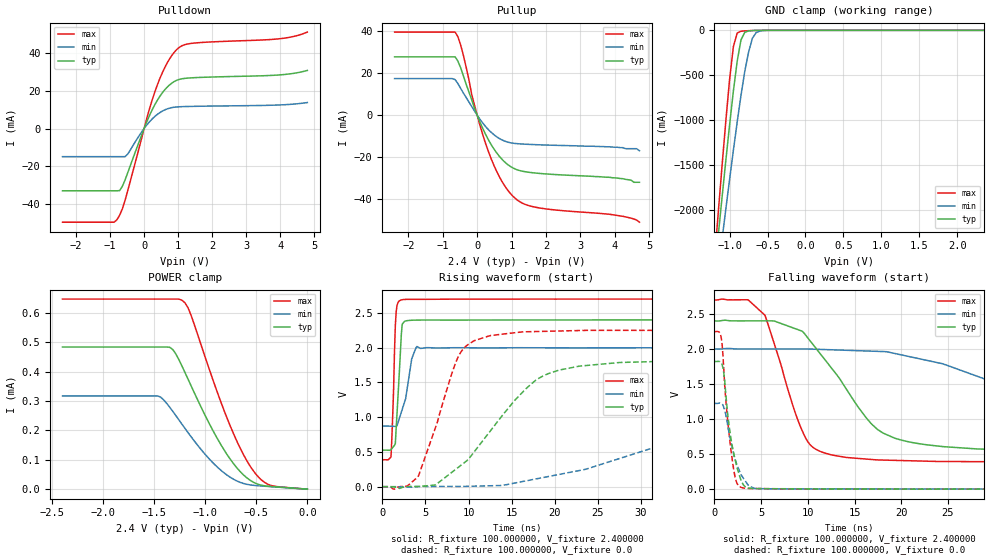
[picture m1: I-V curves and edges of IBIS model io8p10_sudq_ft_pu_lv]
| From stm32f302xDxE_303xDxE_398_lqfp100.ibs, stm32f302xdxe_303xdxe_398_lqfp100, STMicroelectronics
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|   Model io8p10_sudq_ft_pu_lv
[Model]  io8p10_sudq_ft_pu_lv
Model_type I/O
Polarity   Non-Inverting
Enable   Active-Low
Vinl =   0.720000V
Vinh =   1.680000V
Vmeas =  1.200000V
Cref =   50.000000pF
Rref =   100.000000M
Vref =   0.0V
C_comp   1.970100pF   1.887900pF   2.069400pF
[Temperature Range]   25.000000   0.125000k   -40.000000
[Pullup Reference]   2.400000V   2.000000V   2.700000V
[Pulldown Reference]   0.0V   0.0V   0.0V
[POWER Clamp Reference]   2.400000V   2.000000V   2.700000V
[GND Clamp Reference]   0.0V   0.0V   0.0V
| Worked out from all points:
|   slope of the pulldown table from 0 to 0.36 V, typ, clamps not added: 25.5 ohm
|   slope of the pullup table from 0 to 0.36 V, typ, clamps not added: 28.4 ohm
|   GND clamp passes 1 mA (typ) near -0.64 V on its own axis
|   rising waveform, R_fixture 100.000000, V_fixture 2.400000: 20-80 % time 500ps typ, 1.06ns min, 335ps max; typ from 0.527 V to 2.4 V
|   rising waveform, R_fixture 100.000000, V_fixture 0.0: 20-80 % time 7.39ns typ, 21.1ns min, 3.53ns max; typ from 0.001 V to 1.82 V
|   falling waveform, R_fixture 100.000000, V_fixture 2.400000: 20-80 % time 6.28ns typ, 17.7ns min, 3.33ns max; typ from 2.4 V to 0.527 V
|   falling waveform, R_fixture 100.000000, V_fixture 0.0: 20-80 % time 1.16ns typ, 1.4ns min, 916ps max; typ from 1.82 V to 0.001 V
[Pulldown]
|Voltage   I(typ)   I(min)   I(max)
-2.4V     -33.16mA   -14.98mA   -49.86mA
-880mV    -33.16mA   -14.98mA   -49.86mA
-800mV    -33.16mA   -14.98mA   -48.55mA
-640mV    -30.75mA   -14.98mA   -42.77mA
-480mV    -23.43mA   -13.57mA   -32.92mA
80mV      3.651mA    1.905mA    5.506mA
400mV     15.37mA    7.665mA    23.73mA
720mV     22.75mA    10.69mA    36.23mA
1.04V     26.18mA    11.57mA    43.27mA
1.52V     27.09mA    11.81mA    45.55mA
4V        28.55mA    12.55mA    47.81mA
4.8V      30.9mA     13.81mA    51.31mA
[Pullup]
|Voltage   I(typ)   I(min)   I(max)
-2.4V     27.74mA    17.38mA    39.53mA
-640mV    27.74mA    16.88mA    39.53mA
-560mV    25.73mA    15.04mA    37.34mA
-480mV    22.58mA    12.74mA    33.42mA
-80mV     3.427mA    2.071mA    4.957mA
160mV     -6.219mA   -3.715mA   -9.137mA
320mV     -11.51mA   -6.781mA   -16.98mA
720mV     -21mA      -11.8mA    -31.53mA
1.12V     -25.77mA   -13.54mA   -39.82mA
1.76V     -27.69mA   -14.12mA   -44.07mA
3.84V     -29.6mA    -15.1mA    -47.2mA
4.72V     -32mA      -17mA      -51mA
[GND_clamp]
|Voltage   I(typ)   I(min)   I(max)
-2.4V     -9.788A    -9.782A    -9.734A
-1.2V     -2.718A    -3.02A     -2.568A
-1.15V    -2.29A     -2.675A    -2.036A
-1.1V     -1.868A    -2.333A    -1.515A
-1.05V    -1.454A    -1.995A    -1.012A
-950mV    -674.5mA   -1.337A    -180.5mA
-900mV    -345.2mA   -1.023A    -29.72mA
-850mV    -106.4mA   -726mA     -10.13mA
-750mV    -6.396mA   -244mA     -4.026mA
-700mV    -2.558mA   -88.61mA   -2.329mA
-600mV    -416uA     -7.739mA   -368uA
2.35V     0A         0A         0A
[POWER_clamp]
|Voltage   I(typ)   I(min)   I(max)
-2.4V     483.8uA    317.4uA    647uA
-1.47V    483.8uA    317.4uA    647uA
-1.32V    475.6uA    265.2uA    647uA
-1.23V    419.7uA    221.6uA    643.3uA
-1.17V    374.8uA    192.7uA    617.6uA
-1.14V    352.1uA    178.7uA    591.9uA
-840mV    147uA      62.15uA    289.6uA
-690mV    72.24uA    27.76uA    162.7uA
-540mV    25.74uA    13.55uA    67.63uA
-450mV    13.38uA    10.75uA    31.36uA
-360mV    9.231uA    8.535uA    12.97uA
0V        0A         0A         0A
[Ramp]
| variable   typ   min   max
dV/dt_r  1.09257/7.38126n   0.73299/21.13981n   1.34920/3.52606n
dV/dt_f  1.12405/6.26972n   0.67519/17.74591n   1.38687/3.32829n
R_load = 100.000000
[Rising Waveform]
R_fixture= 100.000000
V_fixture= 2.400000
V_fixture_min= 2.000000
V_fixture_max= 2.700000
|time   V(typ)   V(min)   V(max)
0s        526.5mV    872.5mV    388.6mV
1.001ns   534.6mV    870.8mV    428.2mV
1.301ns   580.6mV    869.2mV    1.393V
1.502ns   618.8mV    868.6mV    2.312V
1.702ns   1.058V     879.1mV    2.61V
2.102ns   1.96V      1.035V     2.683V
2.302ns   2.337V     1.113V     2.69V
3.403ns   2.395V     1.84V      2.696V
4.004ns   2.398V     2.018V     2.696V
49.85ns   2.4V       2V         2.7V
[Rising Waveform]
R_fixture= 100.000000
V_fixture= 0.0
V_fixture_min= 0.0
V_fixture_max= 0.0
|time   V(typ)   V(min)   V(max)
0s        1.057mV    1.357mV    941.6uV
2.803ns   2.743mV    -4.311mV   6.043mV
4.204ns   4.237mV    2.829mV    160mV
6.206ns   30.25mV    4.308mV    867.3mV
8.809ns   280mV      4.087mV    1.872V
12.61ns   817.4mV    14.56mV    2.176V
17.82ns   1.535V     112.7mV    2.233V
23.02ns   1.737V     237.9mV    2.248V
49.25ns   1.822V     1.075V     2.25V
99.7ns    1.822V     1.224V     2.25V
[Falling Waveform]
R_fixture= 100.000000
V_fixture= 2.400000
V_fixture_min= 2.000000
V_fixture_max= 2.700000
|time   V(typ)   V(min)   V(max)
0s        2.4V       2V         2.7V
3.604ns   2.401V     2V         2.702V
5.405ns   2.402V     2V         2.482V
9.61ns    2.224V     2V         771.1mV
12.61ns   1.714V     1.989V     487.5mV
17.42ns   856.8mV    1.967V     418.1mV
24.42ns   608.6mV    1.79V      395.7mV
43.84ns   535.4mV    1.055V     388.6mV
52.45ns   528.4mV    947.9mV    388.6mV
99.7ns    526.5mV    872.5mV    388.6mV
[Falling Waveform]
R_fixture= 100.000000
V_fixture= 0.0
V_fixture_min= 0.0
V_fixture_max= 0.0
|time   V(typ)   V(min)   V(max)
0s        1.822V     1.224V     2.25V
700.7ps   1.803V     1.224V     2.181V
800.8ps   1.785V     1.216V     2.099V
1.001ns   1.656V     1.167V     1.707V
1.401ns   1.093V     925.2mV    997.9mV
1.902ns   618.4mV    593.3mV    424.7mV
2.302ns   371.4mV    390.6mV    125.2mV
2.903ns   111.3mV    194.4mV    23.9mV
4.705ns   8.256mV    8.438mV    9.524mV
49.85ns   1.057mV    1.357mV    941.6uV
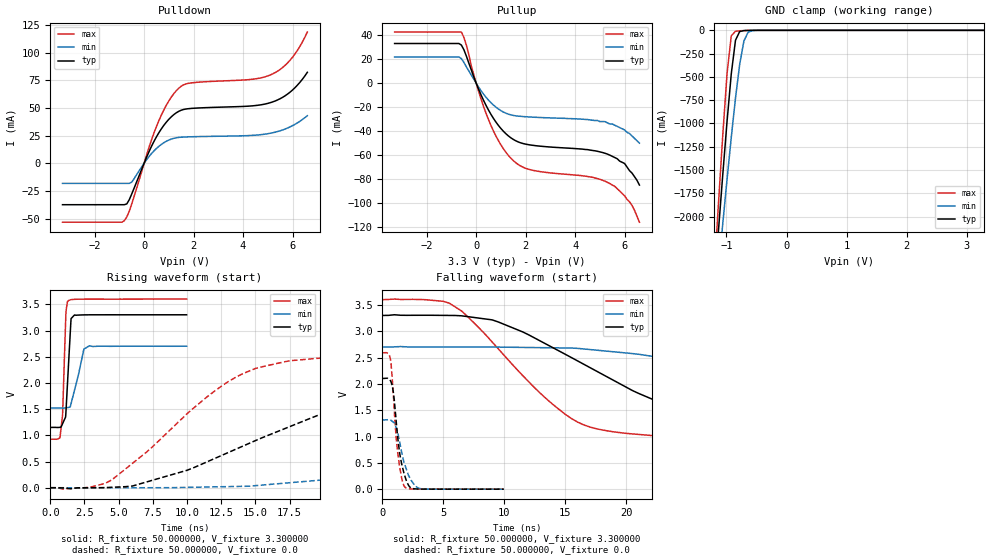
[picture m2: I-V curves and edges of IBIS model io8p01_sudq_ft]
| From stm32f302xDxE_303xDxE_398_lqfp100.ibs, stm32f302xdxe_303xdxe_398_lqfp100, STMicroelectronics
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|   Model io8p01_sudq_ft
[Model]  io8p01_sudq_ft
Model_type I/O
Polarity   Non-Inverting
Enable   Active-Low
Vinl =   0.990000V
Vinh =   2.310000V
Vmeas =  1.650000V
Cref =   50.000000pF
Rref =   100.000000M
Vref =   0.0V
C_comp   1.970900pF   1.892300pF   2.063200pF
[Temperature Range]   25.000000   0.125000k   -40.000000
[Pullup Reference]   3.300000V   2.700000V   3.600000V
[Pulldown Reference]   0.0V   0.0V   0.0V
[POWER Clamp Reference]   3.300000V   2.700000V   3.600000V
[GND Clamp Reference]   0.0V   0.0V   0.0V
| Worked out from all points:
|   slope of the pulldown table from 0 to 0.495 V, typ, clamps not added: 20.9 ohm
|   slope of the pullup table from 0 to 0.495 V, typ, clamps not added: 22.2 ohm
|   GND clamp passes 1 mA (typ) near -0.64 V on its own axis
|   rising waveform, R_fixture 50.000000, V_fixture 3.300000: 20-80 % time 269ps typ, 640ps min, 200ps max; typ from 1.15 V to 3.3 V
|   rising waveform, R_fixture 50.000000, V_fixture 0.0: 20-80 % time 12.5ns typ, 30.4ns min, 7.06ns max; typ from 0 V to 2.1 V
|   falling waveform, R_fixture 50.000000, V_fixture 3.300000: 20-80 % time 10.9ns typ, 22.8ns min, 6.88ns max; typ from 3.3 V to 1.15 V
|   falling waveform, R_fixture 50.000000, V_fixture 0.0: 20-80 % time 666ps typ, 862ps min, 543ps max; typ from 2.1 V to 0 V
[Pulldown]
|Voltage   I(typ)   I(min)   I(max)
-3.3V     -37.45mA   -18.2mA    -53.24mA
-800mV    -37.45mA   -18.2mA    -51.9mA
-700mV    -36.7mA    -18.2mA    -48.48mA
-500mV    -27.71mA   -17.01mA   -36.66mA
200mV     10.57mA    6.084mA    14.57mA
500mV     23.91mA    13.38mA    33.24mA
900mV     37.17mA    19.88mA    52.48mA
1.3V      45.55mA    23.01mA    65.5mA
1.8V      49.29mA    23.83mA    72.18mA
5.1V      54.68mA    27.07mA    79.72mA
5.9V      64.2mA     32.82mA    93.01mA
6.6V      82.13mA    42.97mA    118.4mA
[Pullup]
|Voltage   I(typ)   I(min)   I(max)
-3.3V     33.18mA    21.9mA     42.7mA
-600mV    31.87mA    20.57mA    42.7mA
-400mV    22.78mA    13.76mA    31.89mA
100mV     -5.13mA    -3.299mA   -6.952mA
500mV     -22.5mA    -14.16mA   -30.52mA
900mV     -35.28mA   -21.55mA   -48mA
1.4V      -45.55mA   -26.41mA   -62.54mA
2.2V      -51.57mA   -28.22mA   -72.25mA
5.4V      -60mA      -34mA      -83.7mA
6V        -67mA      -39mA      -94mA
6.2V      -73mA      -42mA      -99mA
6.6V      -85mA      -50mA      -116mA
[GND_clamp]
|Voltage   I(typ)   I(min)   I(max)
-3.3V     -9.525A    -9.501A    -9.513A
-1.2V     -2.719A    -3.023A    -2.568A
-1.13V    -2.122A    -2.541A    -1.826A
-1.06V    -1.537A    -2.065A    -1.111A
-990mV    -975.7mA   -1.599A    -462mA
-920mV    -467.4mA   -1.149A    -59mA
-850mV    -106.6mA   -727.3mA   -10.11mA
-780mV    -13.06mA   -365.4mA   -5.254mA
-710mV    -3.045mA   -114.8mA   -2.635mA
-640mV    -943.2uA   -20.16mA   -905.7uA
-570mV    -199.4uA   -3.959mA   -156.8uA
3.28V     0A         0A         0A
[POWER_clamp]
|Voltage   I(typ)   I(min)   I(max)
-3.28V    0A         0A         0A
0V        0A         0A         0A
[Ramp]
| variable   typ   min   max
dV/dt_r  1.26240/12.53718n   0.78948/30.37625n   1.55460/7.05051n
dV/dt_f  1.28952/10.93890n   0.70650/22.81705n   1.60469/6.86180n
R_load = 50.000000
[Rising Waveform]
R_fixture= 50.000000
V_fixture= 3.300000
V_fixture_min= 2.700000
V_fixture_max= 3.600000
|time   V(typ)   V(min)   V(max)
0s        1.151V     1.522V     925.5mV
720.7ps   1.153V     1.522V     979.3mV
900.9ps   1.222V     1.52V      1.393V
1.141ns   1.422V     1.523V     3.312V
1.261ns   1.999V     1.529V     3.554V
1.522ns   3.228V     1.605V     3.588V
1.762ns   3.294V     1.851V     3.595V
2.462ns   3.298V     2.646V     3.599V
2.863ns   3.3V       2.708V     3.599V
9.97ns    3.3V       2.7V       3.6V
[Rising Waveform]
R_fixture= 50.000000
V_fixture= 0.0
V_fixture_min= 0.0
V_fixture_max= 0.0
|time   V(typ)   V(min)   V(max)
0s        2.028nV    11.57nV    2.55nV
4.505ns   8.246mV    23.61uV    149.8mV
10.01ns   333.3mV    6.624mV    1.413V
14.01ns   785.5mV    26.06mV    2.168V
22.52ns   1.625V     206.1mV    2.53V
28.03ns   1.898V     345.1mV    2.568V
39.54ns   2.061V     685.1mV    2.588V
55.56ns   2.101V     1.054V     2.592V
75.08ns   2.103V     1.24V      2.591V
249.2ns   2.104V     1.316V     2.591V
[Falling Waveform]
R_fixture= 50.000000
V_fixture= 3.300000
V_fixture_min= 2.700000
V_fixture_max= 3.600000
|time   V(typ)   V(min)   V(max)
0s        3.3V       2.7V       3.6V
5.506ns   3.3V       2.701V     3.532V
9.009ns   3.216V     2.7V       2.797V
13.01ns   2.808V     2.688V     1.811V
16.02ns   2.437V     2.675V     1.275V
22.52ns   1.673V     2.511V     1.015V
30.53ns   1.307V     2.227V     958.1mV
45.05ns   1.189V     1.779V     932.1mV
69.57ns   1.157V     1.587V     925.7mV
249.2ns   1.151V     1.522V     925.5mV
[Falling Waveform]
R_fixture= 50.000000
V_fixture= 0.0
V_fixture_min= 0.0
V_fixture_max= 0.0
|time   V(typ)   V(min)   V(max)
0s        2.104V     1.316V     2.591V
660.7ps   2.062V     1.315V     2.466V
900.9ps   1.84V      1.273V     1.796V
1.141ns   1.275V     1.165V     952.9mV
1.261ns   977.3mV    1.075V     694.5mV
1.602ns   464.8mV    685.7mV    192.5mV
1.862ns   238.4mV    452mV      36.35mV
2.282ns   34.71mV    203.8mV    5.722mV
3.103ns   2.027mV    11.23mV    1.089mV
9.97ns    2.028nV    11.57nV    2.55nV
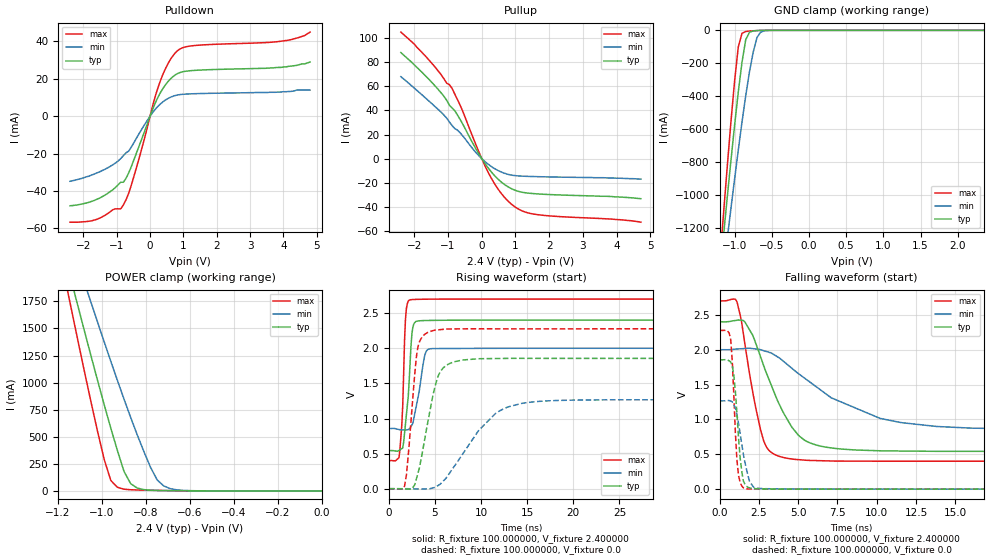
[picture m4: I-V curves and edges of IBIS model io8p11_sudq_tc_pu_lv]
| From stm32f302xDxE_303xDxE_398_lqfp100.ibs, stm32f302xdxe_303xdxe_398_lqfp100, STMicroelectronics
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|   Model io8p11_sudq_tc_pu_lv
[Model]  io8p11_sudq_tc_pu_lv
Model_type I/O
Polarity   Non-Inverting
Enable   Active-Low
Vinl =   0.720000V
Vinh =   1.680000V
Vmeas =  1.200000V
Cref =   50.000000pF
Rref =   100.000000M
Vref =   0.0V
C_comp   1.378000pF   1.292700pF   1.486400pF
[Temperature Range]   25.000000   0.125000k   -40.000000
[Pullup Reference]   2.400000V   2.000000V   2.700000V
[Pulldown Reference]   0.0V   0.0V   0.0V
[POWER Clamp Reference]   2.400000V   2.000000V   2.700000V
[GND Clamp Reference]   0.0V   0.0V   0.0V
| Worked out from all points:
|   slope of the pulldown table from 0 to 0.36 V, typ, clamps not added: 25.7 ohm
|   slope of the pullup table from 0 to 0.36 V, typ, clamps not added: 26.8 ohm
|   GND clamp passes 1 mA (typ) near -0.67 V on its own axis
|   POWER clamp passes 1 mA (typ) near -0.60 V on its own axis
|   rising waveform, R_fixture 100.000000, V_fixture 2.400000: 20-80 % time 602ps typ, 875ps min, 369ps max; typ from 0.543 V to 2.4 V
|   rising waveform, R_fixture 100.000000, V_fixture 0.0: 20-80 % time 1.64ns typ, 4.38ns min, 858ps max; typ from 0.001 V to 1.86 V
|   falling waveform, R_fixture 100.000000, V_fixture 2.400000: 20-80 % time 2.13ns typ, 5.08ns min, 1.09ns max; typ from 2.4 V to 0.543 V
|   falling waveform, R_fixture 100.000000, V_fixture 0.0: 20-80 % time 379ps typ, 598ps min, 284ps max; typ from 1.86 V to 0.001 V
[Pulldown]
|Voltage   I(typ)   I(min)   I(max)
-2.4V     -47.9mA    -34.8mA    -56.7mA
-1.6V     -44.5mA    -30.4mA    -55.2mA
-880mV    -35.33mA   -22.63mA   -49.55mA
-800mV    -35.33mA   -21.13mA   -47.42mA
-640mV    -30.33mA   -18.65mA   -41.16mA
-480mV    -23.12mA   -14mA      -31.94mA
240mV     10.22mA    5.339mA    15.38mA
480mV     17.22mA    8.864mA    26.1mA
800mV     22.59mA    11.27mA    34.68mA
1.28V     24.44mA    12mA       37.7mA
4.16V     26.7mA     13.2mA     40.7mA
4.8V      29mA       14mA       45mA
[Pullup]
|Voltage   I(typ)   I(min)   I(max)
-2.4V     88mA       68mA       105mA
-2V       77.8mA     58.5mA     95mA
-1.36V    59.6mA     42.5mA     75.1mA
-880mV    42.12mA    27.44mA    58.22mA
-560mV    28.45mA    18.75mA    39mA
-160mV    7.44mA     4.66mA     10.64mA
160mV     -6.607mA   -3.947mA   -9.704mA
480mV     -16.91mA   -9.806mA   -25.1mA
880mV     -24.89mA   -13.63mA   -37.75mA
1.2V      -27.87mA   -14.5mA    -43.37mA
1.6V      -29.13mA   -14.89mA   -46.24mA
4.72V     -33.2mA    -17mA      -52.7mA
[GND_clamp]
|Voltage   I(typ)   I(min)   I(max)
-2.4V     -7.358A    -6.372A    -8.78A
-1.2V     -1.489A    -1.65A     -1.416A
-1.15V    -1.254A    -1.461A    -1.124A
-1.1V     -1.024A    -1.273A    -838.2mA
-1.05V    -797.6mA   -1.088A    -563.1mA
-950mV    -374.6mA   -728.7mA   -100.8mA
-900mV    -194.3mA   -557.9mA   -18.01mA
-850mV    -56.94mA   -397.4mA   -7.08mA
-750mV    -3.582mA   -133.8mA   -2.771mA
-700mV    -1.516mA   -44.7mA    -1.516mA
-600mV    -235.4uA   -2.939mA   -209.5uA
2.35V     0A         0A         0A
[POWER_clamp]
|Voltage   I(typ)   I(min)   I(max)
-2.4V     9.979A     9.967A     9.901A
-1.17V    2.182A     2.481A     1.978A
-1.14V    1.945A     2.294A     1.683A
-1.11V    1.71A      2.108A     1.391A
-1.08V    1.476A     1.923A     1.102A
-1.05V    1.245A     1.739A     819.9mA
-960mV    578.3mA    1.196A     96.08mA
-900mV    179.5mA    846.7mA    16.05mA
-870mV    67.19mA    678.8mA    10.83mA
-780mV    6.763mA    219.9mA    5.868mA
-720mV    3.368mA    46.35mA    3.823mA
0V        0A         0A         0A
[Ramp]
| variable   typ   min   max
dV/dt_r  1.11279/1.64269n   0.75936/4.37377n   1.36532/0.85552n
dV/dt_f  1.11416/2.12761n   0.68574/5.07653n   1.37891/1.09224n
R_load = 100.000000
[Rising Waveform]
R_fixture= 100.000000
V_fixture= 2.400000
V_fixture_min= 2.000000
V_fixture_max= 2.700000
|time   V(typ)   V(min)   V(max)
0s        543.1mV    857mV      401.7mV
1.101ns   544.9mV    843.3mV    443.6mV
1.502ns   580.3mV    838.3mV    1.175V
1.802ns   923.2mV    838.2mV    2.416V
2.302ns   1.794V     867.3mV    2.689V
2.503ns   2.209V     910.4mV    2.692V
2.703ns   2.345V     998.6mV    2.694V
3.904ns   2.394V     1.905V     2.698V
4.404ns   2.396V     1.991V     2.699V
49.85ns   2.4V       2V         2.7V
[Rising Waveform]
R_fixture= 100.000000
V_fixture= 0.0
V_fixture_min= 0.0
V_fixture_max= 0.0
|time   V(typ)   V(min)   V(max)
0s        956.5uV    1.197mV    860.5uV
1.702ns   -1.917mV   1.129mV    40.17mV
2.002ns   -4.309mV   1.024mV    331.4mV
3.103ns   197.3mV    -1.902mV   1.984V
4.304ns   1.005V     -1.209mV   2.231V
5.305ns   1.59V      44.63mV    2.262V
6.306ns   1.762V     171.3mV    2.274V
11.51ns   1.854V     1.065V     2.276V
14.41ns   1.856V     1.215V     2.276V
49.85ns   1.856V     1.267V     2.276V
[Falling Waveform]
R_fixture= 100.000000
V_fixture= 2.400000
V_fixture_min= 2.000000
V_fixture_max= 2.700000
|time   V(typ)   V(min)   V(max)
0s        2.4V       2V         2.7V
1.101ns   2.422V     2.01V      2.688V
2.102ns   2.208V     2.016V     1.395V
2.803ns   1.77V      1.986V     692.3mV
4.104ns   1.079V     1.826V     452.4mV
5.105ns   754.8mV    1.643V     422.5mV
6.306ns   624.6mV    1.443V     409.7mV
10.21ns   551mV      1.016V     401.7mV
13.81ns   543.3mV    899.7mV    401.6mV
49.85ns   543.1mV    857mV      401.7mV
[Falling Waveform]
R_fixture= 100.000000
V_fixture= 0.0
V_fixture_min= 0.0
V_fixture_max= 0.0
|time   V(typ)   V(min)   V(max)
0s        1.856V     1.267V     2.276V
700.7ps   1.824V     1.265V     2.145V
800.8ps   1.77V      1.252V     1.84V
900.9ps   1.637V     1.21V      1.347V
1.101ns   1.074V     1.066V     409.7mV
1.301ns   452.3mV    798.5mV    97.86mV
1.602ns   72.98mV    389.7mV    10.53mV
2.102ns   11.98mV    47.24mV    2.972mV
2.803ns   3.939mV    8.329mV    1.89mV
49.85ns   956.5uV    1.197mV    860.5uV
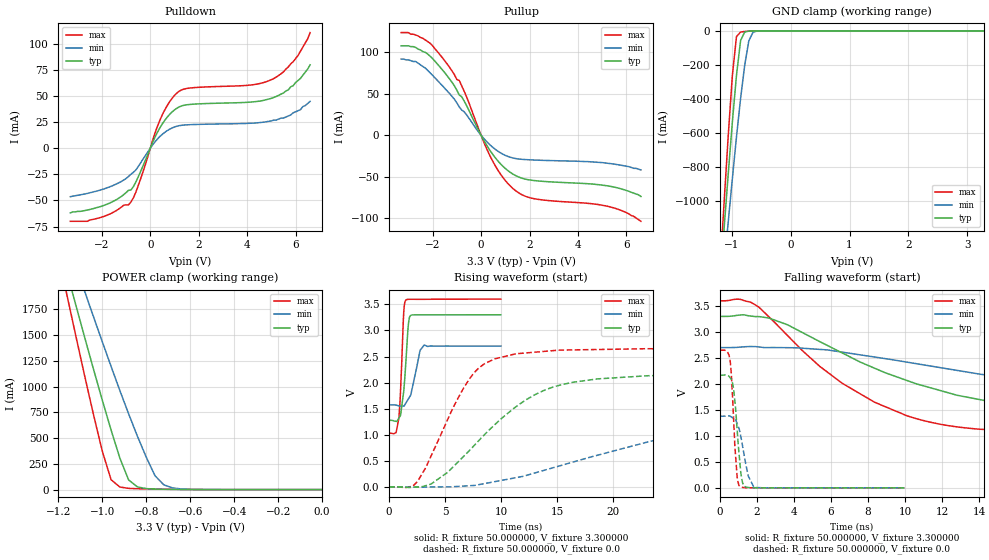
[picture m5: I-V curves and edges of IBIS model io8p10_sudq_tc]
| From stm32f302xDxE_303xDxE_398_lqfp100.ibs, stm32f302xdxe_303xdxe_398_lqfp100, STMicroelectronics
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|   Model io8p10_sudq_tc
[Model]  io8p10_sudq_tc
Model_type I/O
Polarity   Non-Inverting
Enable   Active-Low
Vinl =   0.990000V
Vinh =   2.310000V
Vmeas =  1.650000V
Cref =   50.000000pF
Rref =   100.000000M
Vref =   0.0V
C_comp   1.329900pF   1.255600pF   1.431200pF
[Temperature Range]   25.000000   0.125000k   -40.000000
[Pullup Reference]   3.300000V   2.700000V   3.600000V
[Pulldown Reference]   0.0V   0.0V   0.0V
[POWER Clamp Reference]   3.300000V   2.700000V   3.600000V
[GND Clamp Reference]   0.0V   0.0V   0.0V
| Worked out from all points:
|   slope of the pulldown table from 0 to 0.495 V, typ, clamps not added: 21.3 ohm
|   slope of the pullup table from 0 to 0.495 V, typ, clamps not added: 20.9 ohm
|   GND clamp passes 1 mA (typ) near -0.67 V on its own axis
|   POWER clamp passes 1 mA (typ) near -0.60 V on its own axis
|   rising waveform, R_fixture 50.000000, V_fixture 3.300000: 20-80 % time 430ps typ, 663ps min, 305ps max; typ from 1.27 V to 3.3 V
|   rising waveform, R_fixture 50.000000, V_fixture 0.0: 20-80 % time 6.79ns typ, 16.1ns min, 3.72ns max; typ from 0 V to 2.17 V
|   falling waveform, R_fixture 50.000000, V_fixture 3.300000: 20-80 % time 9.36ns typ, 15.6ns min, 5.83ns max; typ from 3.3 V to 1.27 V
|   falling waveform, R_fixture 50.000000, V_fixture 0.0: 20-80 % time 301ps typ, 442ps min, 235ps max; typ from 2.17 V to 0 V
[Pulldown]
|Voltage   I(typ)   I(min)   I(max)
-3.3V     -62mA      -46.4mA    -70mA
-2V       -55.5mA    -39.6mA    -66mA
-800mV    -40.04mA   -24.89mA   -51.58mA
-500mV    -27.57mA   -17.6mA    -36.07mA
400mV     19.71mA    11.36mA    27.01mA
700mV     29.83mA    16.93mA    40.97mA
1.1V      38.46mA    21.2mA     53.02mA
1.6V      41.98mA    22.62mA    57.7mA
4.1V      44.26mA    24mA       60.59mA
5V        47.9mA     26.3mA     65.8mA
5.9V      60mA       34mA       83mA
6.6V      80mA       45mA       111mA
[Pullup]
|Voltage   I(typ)   I(min)   I(max)
-3.3V     108mA      92mA       124mA
-2.7V     106mA      89mA       121mA
-2.2V     98mA       78.2mA     113mA
-1.4V     71.8mA     53.5mA     86.1mA
-900mV    48.51mA    34.23mA    66.14mA
-700mV    41.33mA    28.36mA    53.31mA
400mV     -19.77mA   -12.52mA   -26.8mA
900mV     -37.48mA   -22.89mA   -50.99mA
1.4V      -48.39mA   -28.06mA   -66.43mA
2.2V      -54.79mA   -29.98mA   -76.75mA
5.3V      -61.6mA    -34.2mA    -86.4mA
6.6V      -74mA      -42mA      -104mA
[GND_clamp]
|Voltage   I(typ)   I(min)   I(max)
-3.3V     -9.739A    -9.975A    -9.587A
-1.2V     -1.489A    -1.65A     -1.416A
-1.13V    -1.162A    -1.385A    -1.009A
-1.06V    -842.2mA   -1.125A    -616.9mA
-990mV    -537.1mA   -870.1mA   -263mA
-920mV    -262.4mA   -625.3mA   -33.96mA
-850mV    -56.94mA   -397.4mA   -7.08mA
-780mV    -7.011mA   -202.2mA   -3.71mA
-710mV    -1.778mA   -58.23mA   -1.736mA
-640mV    -550uA     -8.783mA   -542.4uA
-570mV    -109.8uA   -1.292mA   -86.89uA
3.28V     0A         0A         0A
[POWER_clamp]
|Voltage   I(typ)   I(min)   I(max)
-3.28V    9.897A     9.838A     9.594A
-1.16V    2.103A     2.419A     1.88A
-1.12V    1.788A     2.17A      1.488A
-1.08V    1.476A     1.923A     1.102A
-1V       868.1mA    1.435A     373.1mA
-960mV    578.2mA    1.196A     96.06mA
-880mV    93.24mA    734.1mA    12.01mA
-840mV    26.3mA     517.4mA    8.56mA
-760mV    5.106mA    134mA      5.119mA
-720mV    3.355mA    46.34mA    3.808mA
-600mV    1.005mA    2.564mA    1.072mA
0V        0A         0A         0A
[Ramp]
| variable   typ   min   max
dV/dt_r  1.30062/6.78457n   0.81108/16.38189n   1.58898/3.72049n
dV/dt_f  1.21476/9.34677n   0.66966/15.73456n   1.54236/5.82007n
R_load = 50.000000
[Rising Waveform]
R_fixture= 50.000000
V_fixture= 3.300000
V_fixture_min= 2.700000
V_fixture_max= 3.600000
|time   V(typ)   V(min)   V(max)
0s        1.275V     1.571V     1.03V
620.6ps   1.257V     1.567V     1.042V
860.9ps   1.316V     1.555V     1.316V
981ps     1.359V     1.551V     1.678V
1.301ns   1.833V     1.548V     3.349V
1.481ns   2.359V     1.604V     3.579V
1.822ns   3.257V     1.724V     3.597V
2.763ns   3.299V     2.618V     3.596V
3.123ns   3.299V     2.719V     3.596V
9.97ns    3.3V       2.7V       3.6V
[Rising Waveform]
R_fixture= 50.000000
V_fixture= 0.0
V_fixture_min= 0.0
V_fixture_max= 0.0
|time   V(typ)   V(min)   V(max)
0s        1.051nV    9.611nV    1.582nV
2.503ns   -539.6uV   -4.779mV   100.5mV
3.804ns   64.2mV     -615.8uV   621.6mV
6.807ns   620.6mV    17.89mV    1.95V
8.008ns   889.3mV    43.28mV    2.28V
9.409ns   1.189V     99.91mV    2.454V
13.81ns   1.849V     317.1mV    2.598V
18.62ns   2.071V     608.8mV    2.634V
32.83ns   2.164V     1.213V     2.648V
49.85ns   2.167V     1.378V     2.648V
[Falling Waveform]
R_fixture= 50.000000
V_fixture= 3.300000
V_fixture_min= 2.700000
V_fixture_max= 3.600000
|time   V(typ)   V(min)   V(max)
0s        3.3V       2.7V       3.6V
1.101ns   3.327V     2.709V     3.628V
2.002ns   3.296V     2.716V     3.502V
3.604ns   3.145V     2.698V     2.949V
5.405ns   2.812V     2.664V     2.335V
8.308ns   2.31V      2.521V     1.657V
12.61ns   1.802V     2.272V     1.183V
21.22ns   1.381V     1.891V     1.048V
30.33ns   1.29V      1.686V     1.032V
49.85ns   1.275V     1.571V     1.03V
[Falling Waveform]
R_fixture= 50.000000
V_fixture= 0.0
V_fixture_min= 0.0
V_fixture_max= 0.0
|time   V(typ)   V(min)   V(max)
0s        2.167V     1.378V     2.648V
400.4ps   2.16V      1.384V     2.616V
560.6ps   2.114V     1.377V     2.413V
740.7ps   1.889V     1.335V     1.282V
920.9ps   1.152V     1.243V     240.3mV
1.081ns   458.2mV    1.064V     27.17mV
1.301ns   36.03mV    640.9mV    4.609mV
1.522ns   7.375mV    237.3mV    1.45mV
1.842ns   1.176mV    6.684mV    970.3uV
9.97ns    1.051nV    9.611nV    1.582nV
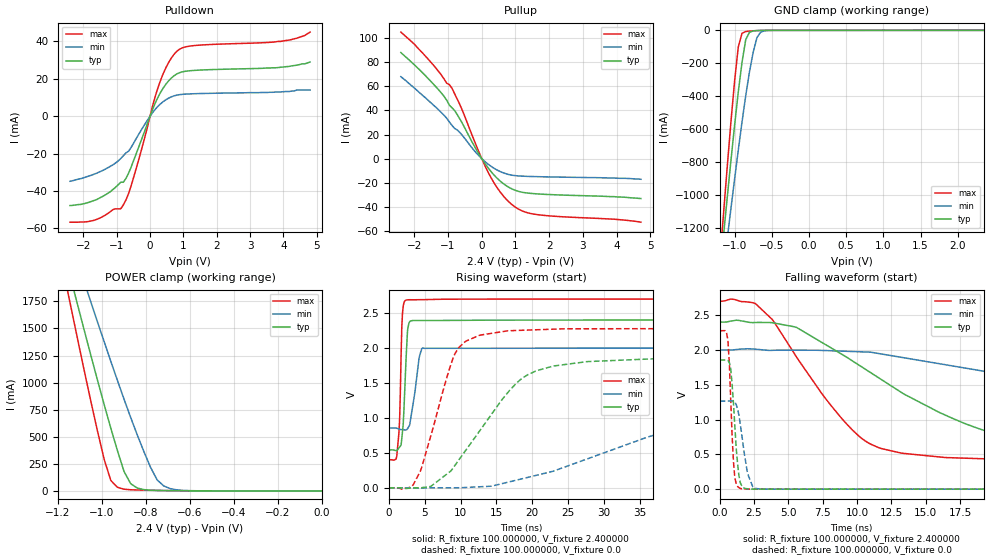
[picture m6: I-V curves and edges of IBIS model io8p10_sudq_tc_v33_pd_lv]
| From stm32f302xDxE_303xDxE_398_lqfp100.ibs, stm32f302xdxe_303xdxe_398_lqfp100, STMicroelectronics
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|   Model io8p10_sudq_tc_v33_pd_lv
[Model]  io8p10_sudq_tc_v33_pd_lv
Model_type I/O
Polarity   Non-Inverting
Enable   Active-Low
Vinl =   0.720000V
Vinh =   1.680000V
Vmeas =  1.200000V
Cref =   50.000000pF
Rref =   100.000000M
Vref =   0.0V
C_comp   1.373400pF   1.288200pF   1.481900pF
[Temperature Range]   25.000000   0.125000k   -40.000000
[Pullup Reference]   2.400000V   2.000000V   2.700000V
[Pulldown Reference]   0.0V   0.0V   0.0V
[POWER Clamp Reference]   2.400000V   2.000000V   2.700000V
[GND Clamp Reference]   0.0V   0.0V   0.0V
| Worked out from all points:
|   slope of the pulldown table from 0 to 0.36 V, typ, clamps not added: 25.7 ohm
|   slope of the pullup table from 0 to 0.36 V, typ, clamps not added: 26.8 ohm
|   GND clamp passes 1 mA (typ) near -0.67 V on its own axis
|   POWER clamp passes 1 mA (typ) near -0.60 V on its own axis
|   rising waveform, R_fixture 100.000000, V_fixture 2.400000: 20-80 % time 488ps typ, 920ps min, 350ps max; typ from 0.541 V to 2.4 V
|   rising waveform, R_fixture 100.000000, V_fixture 0.0: 20-80 % time 8.11ns typ, 22.7ns min, 3.8ns max; typ from 0 V to 1.85 V
|   falling waveform, R_fixture 100.000000, V_fixture 2.400000: 20-80 % time 10.1ns typ, 23.6ns min, 5.13ns max; typ from 2.4 V to 0.541 V
|   falling waveform, R_fixture 100.000000, V_fixture 0.0: 20-80 % time 390ps typ, 567ps min, 290ps max; typ from 1.85 V to 0 V
[Pulldown]
|Voltage   I(typ)   I(min)   I(max)
-2.4V     -47.8mA    -34.8mA    -56.7mA
-1.68V    -45.1mA    -31mA      -55.7mA
-1.12V    -39.3mA    -26.1mA    -50.03mA
-800mV    -35.33mA   -21.13mA   -47.42mA
-640mV    -30.33mA   -18.65mA   -41.16mA
-480mV    -23.12mA   -14mA      -31.94mA
240mV     10.22mA    5.339mA    15.38mA
480mV     17.22mA    8.864mA    26.1mA
800mV     22.59mA    11.27mA    34.68mA
1.36V     24.54mA    12.05mA    37.84mA
3.92V     26.2mA     13mA       40mA
4.8V      29mA       14mA       45mA
[Pullup]
|Voltage   I(typ)   I(min)   I(max)
-2.4V     88mA       68mA       105mA
-2V       77.9mA     58.6mA     95mA
-1.36V    59.6mA     42.6mA     75.1mA
-880mV    42.13mA    27.44mA    58.22mA
-560mV    28.45mA    18.75mA    39mA
-160mV    7.44mA     4.66mA     10.64mA
160mV     -6.607mA   -3.947mA   -9.704mA
480mV     -16.91mA   -9.806mA   -25.1mA
880mV     -24.89mA   -13.63mA   -37.75mA
1.2V      -27.87mA   -14.5mA    -43.37mA
1.6V      -29.13mA   -14.89mA   -46.24mA
4.72V     -33.1mA    -17.1mA    -52.7mA
[GND_clamp]
|Voltage   I(typ)   I(min)   I(max)
-2.4V     -7.358A    -6.372A    -8.78A
-1.2V     -1.489A    -1.65A     -1.416A
-1.15V    -1.254A    -1.461A    -1.124A
-1.1V     -1.024A    -1.273A    -838.2mA
-1.05V    -797.6mA   -1.088A    -563.2mA
-950mV    -374.6mA   -728.7mA   -100.8mA
-900mV    -194.3mA   -558mA     -18.03mA
-850mV    -56.96mA   -397.5mA   -7.097mA
-750mV    -3.597mA   -133.8mA   -2.788mA
-700mV    -1.53mA    -44.71mA   -1.533mA
-600mV    -249.2uA   -2.951mA   -225.1uA
2.35V     60.02uA    46.69uA    67.1uA
[POWER_clamp]
|Voltage   I(typ)   I(min)   I(max)
-2.4V     9.979A     9.967A     9.901A
-1.17V    2.182A     2.481A     1.978A
-1.14V    1.945A     2.294A     1.683A
-1.11V    1.71A      2.108A     1.391A
-1.08V    1.476A     1.923A     1.102A
-1.05V    1.245A     1.739A     819.9mA
-960mV    578.2mA    1.196A     96.06mA
-900mV    179.5mA    846.7mA    16.04mA
-870mV    67.18mA    678.8mA    10.82mA
-780mV    6.749mA    219.9mA    5.853mA
-720mV    3.355mA    46.34mA    3.808mA
0V        0A         0A         0A
[Ramp]
| variable   typ   min   max
dV/dt_r  1.11228/8.10508n   0.75684/22.66815n   1.36500/3.79210n
dV/dt_f  1.11451/10.12129n   0.68717/23.63424n   1.37930/5.12026n
R_load = 100.000000
[Rising Waveform]
R_fixture= 100.000000
V_fixture= 2.400000
V_fixture_min= 2.000000
V_fixture_max= 2.700000
|time   V(typ)   V(min)   V(max)
0s        541.2mV    853.5mV    400.3mV
1.101ns   529.8mV    851.5mV    449.6mV
1.502ns   582.6mV    837.6mV    979.4mV
1.802ns   698.4mV    831.1mV    2.286V
1.902ns   803.9mV    830.2mV    2.498V
2.402ns   1.85V      827.7mV    2.684V
2.603ns   2.246V     843.6mV    2.688V
2.803ns   2.355V     880.2mV    2.689V
4.705ns   2.392V     1.999V     2.691V
49.85ns   2.399V     1.999V     2.699V
[Rising Waveform]
R_fixture= 100.000000
V_fixture= 0.0
V_fixture_min= 0.0
V_fixture_max= 0.0
|time   V(typ)   V(min)   V(max)
0s        765pV      13.32nV    588.1pV
3.403ns   -1.551mV   -2.885mV   42.84mV
4.605ns   1.363mV    -4.456mV   298.7mV
9.209ns   318.5mV    125.8uV    1.914V
12.81ns   834.5mV    14.89mV    2.184V
18.82ns   1.581V     134.5mV    2.253V
27.63ns   1.804V     411.3mV    2.274V
45.65ns   1.85V      1.002V     2.275V
53.25ns   1.854V     1.133V     2.275V
99.7ns    1.854V     1.264V     2.275V
[Falling Waveform]
R_fixture= 100.000000
V_fixture= 2.400000
V_fixture_min= 2.000000
V_fixture_max= 2.700000
|time   V(typ)   V(min)   V(max)
0s        2.399V     1.999V     2.699V
2.603ns   2.393V     2.01V      2.664V
5.606ns   2.321V     1.995V     1.893V
9.61ns    1.848V     1.977V     860.1mV
11.01ns   1.67V      1.966V     644.7mV
13.41ns   1.365V     1.886V     513mV
20.62ns   768.2mV    1.643V     427.5mV
29.63ns   594.7mV    1.324V     406.2mV
57.06ns   541.3mV    915.6mV    400.5mV
99.7ns    541.2mV    853.5mV    400.3mV
[Falling Waveform]
R_fixture= 100.000000
V_fixture= 0.0
V_fixture_min= 0.0
V_fixture_max= 0.0
|time   V(typ)   V(min)   V(max)
0s        1.854V     1.264V     2.275V
600.6ps   1.85V      1.265V     2.133V
800.8ps   1.731V     1.269V     1.292V
1.001ns   1.236V     1.263V     400.6mV
1.101ns   907.8mV    1.249V     161.9mV
1.401ns   192.5mV    1.063V     20.53mV
1.602ns   49.53mV    789.2mV    6.16mV
2.102ns   3.635mV    186mV      1.085mV
2.903ns   590.2uV    4.312mV    1.058mV
49.85ns   765pV      13.32nV    588.1pV
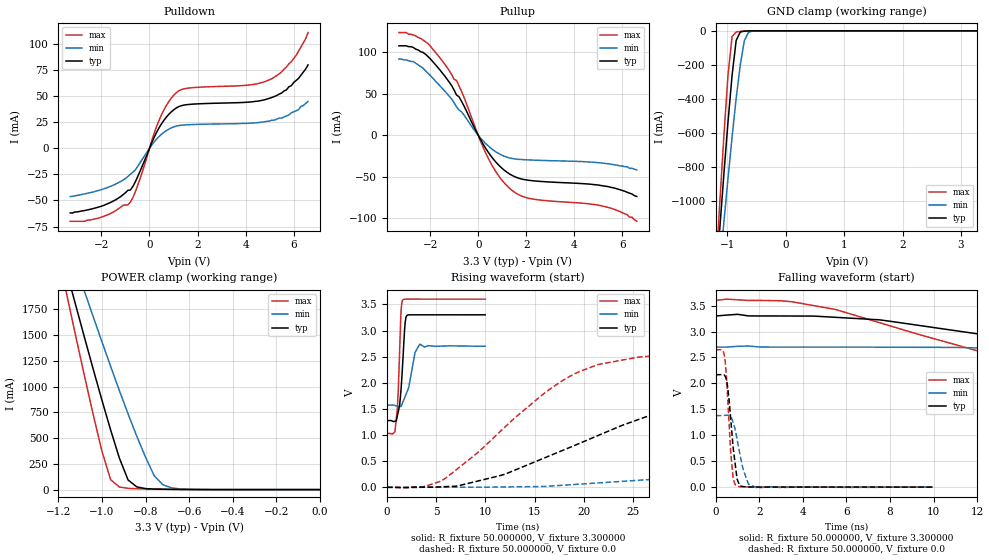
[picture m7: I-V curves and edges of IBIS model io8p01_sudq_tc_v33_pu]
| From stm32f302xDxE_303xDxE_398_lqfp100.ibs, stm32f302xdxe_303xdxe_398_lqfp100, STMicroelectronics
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|   Model io8p01_sudq_tc_v33_pu
[Model]  io8p01_sudq_tc_v33_pu
Model_type I/O
Polarity   Non-Inverting
Enable   Active-Low
Vinl =   0.990000V
Vinh =   2.310000V
Vmeas =  1.650000V
Cref =   50.000000pF
Rref =   100.000000M
Vref =   0.0V
C_comp   1.325200pF   1.251200pF   1.426700pF
[Temperature Range]   25.000000   0.125000k   -40.000000
[Pullup Reference]   3.300000V   2.700000V   3.600000V
[Pulldown Reference]   0.0V   0.0V   0.0V
[POWER Clamp Reference]   3.300000V   2.700000V   3.600000V
[GND Clamp Reference]   0.0V   0.0V   0.0V
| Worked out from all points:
|   slope of the pulldown table from 0 to 0.495 V, typ, clamps not added: 21.3 ohm
|   slope of the pullup table from 0 to 0.495 V, typ, clamps not added: 20.9 ohm
|   GND clamp passes 1 mA (typ) near -0.67 V on its own axis
|   POWER clamp passes 1 mA (typ) near -0.60 V on its own axis
|   rising waveform, R_fixture 50.000000, V_fixture 3.300000: 20-80 % time 413ps typ, 774ps min, 302ps max; typ from 1.28 V to 3.3 V
|   rising waveform, R_fixture 50.000000, V_fixture 0.0: 20-80 % time 18.6ns typ, 46.7ns min, 10.2ns max; typ from 0.001 V to 2.17 V
|   falling waveform, R_fixture 50.000000, V_fixture 3.300000: 20-80 % time 26.2ns typ, 44.8ns min, 16.4ns max; typ from 3.3 V to 1.28 V
|   falling waveform, R_fixture 50.000000, V_fixture 0.0: 20-80 % time 298ps typ, 421ps min, 225ps max; typ from 2.17 V to 0.001 V
[Pulldown]
|Voltage   I(typ)   I(min)   I(max)
-3.3V     -62mA      -46.3mA    -70mA
-2.1V     -56.2mA    -40.3mA    -66.8mA
-800mV    -40.05mA   -24.9mA    -51.58mA
-500mV    -27.57mA   -17.6mA    -36.07mA
400mV     19.71mA    11.36mA    27.01mA
700mV     29.83mA    16.93mA    40.97mA
1.1V      38.46mA    21.2mA     53.02mA
1.6V      41.98mA    22.62mA    57.7mA
4.1V      44.26mA    24mA       60.59mA
5V        48mA       26.2mA     65.8mA
5.9V      60mA       34mA       83mA
6.6V      80mA       45mA       111mA
[Pullup]
|Voltage   I(typ)   I(min)   I(max)
-3.3V     108mA      92mA       124mA
-2.7V     106mA      89mA       121mA
-2.2V     98mA       78.1mA     113mA
-1.4V     71.8mA     53.5mA     86.1mA
-900mV    48.5mA     34.23mA    66.14mA
-700mV    41.33mA    28.36mA    53.31mA
400mV     -19.77mA   -12.52mA   -26.8mA
900mV     -37.48mA   -22.89mA   -50.99mA
1.4V      -48.39mA   -28.06mA   -66.43mA
2.2V      -54.79mA   -29.98mA   -76.75mA
5.3V      -61.6mA    -34.1mA    -86.4mA
6.6V      -74mA      -42mA      -104mA
[GND_clamp]
|Voltage   I(typ)   I(min)   I(max)
-3.3V     -9.739A    -9.975A    -9.587A
-1.2V     -1.489A    -1.65A     -1.416A
-1.13V    -1.162A    -1.385A    -1.009A
-1.06V    -842.2mA   -1.125A    -616.9mA
-990mV    -537.1mA   -870.1mA   -263mA
-920mV    -262.4mA   -625.3mA   -33.96mA
-850mV    -56.94mA   -397.4mA   -7.08mA
-780mV    -7.011mA   -202.2mA   -3.71mA
-710mV    -1.778mA   -58.23mA   -1.736mA
-640mV    -550uA     -8.783mA   -542.4uA
-570mV    -109.8uA   -1.292mA   -86.89uA
3.28V     0A         0A         0A
[POWER_clamp]
|Voltage   I(typ)   I(min)   I(max)
-3.28V    9.897A     9.838A     9.594A
-1.16V    2.103A     2.419A     1.88A
-1.12V    1.788A     2.17A      1.488A
-1.08V    1.476A     1.923A     1.102A
-1V       868.2mA    1.435A     373.1mA
-960mV    578.3mA    1.196A     96.08mA
-880mV    93.25mA    734.2mA    12.03mA
-840mV    26.31mA    517.4mA    8.576mA
-760mV    5.12mA     134mA      5.134mA
-720mV    3.368mA    46.35mA    3.823mA
-600mV    1.018mA    2.575mA    1.086mA
0V        0A         0A         0A
[Ramp]
| variable   typ   min   max
dV/dt_r  1.30025/18.58906n   0.82757/46.69142n   1.58870/10.20546n
dV/dt_f  1.21404/26.20609n   0.67698/44.51801n   1.54164/16.37482n
R_load = 50.000000
[Rising Waveform]
R_fixture= 50.000000
V_fixture= 3.300000
V_fixture_min= 2.700000
V_fixture_max= 3.600000
|time   V(typ)   V(min)   V(max)
0s        1.277V     1.572V     1.031V
820.8ps   1.266V     1.565V     1.096V
1.061ns   1.378V     1.552V     1.537V
1.281ns   1.57V      1.549V     2.604V
1.441ns   1.918V     1.553V     3.419V
1.602ns   2.403V     1.627V     3.583V
1.942ns   3.263V     1.784V     3.6V
2.843ns   3.3V       2.576V     3.6V
3.323ns   3.3V       2.736V     3.6V
9.97ns    3.3V       2.7V       3.6V
[Rising Waveform]
R_fixture= 50.000000
V_fixture= 0.0
V_fixture_min= 0.0
V_fixture_max= 0.0
|time   V(typ)   V(min)   V(max)
0s        1.014mV    1.116mV    973.4uV
5.506ns   10.1mV     2.843mV    121.6mV
12.01ns   253.5mV    8.005mV    1.159V
19.52ns   838.4mV    60.86mV    2.212V
25.53ns   1.296V     135.4mV    2.491V
33.03ns   1.739V     269mV      2.588V
50.05ns   2.082V     628.8mV    2.643V
85.59ns   2.16V      1.167V     2.649V
108.1ns   2.169V     1.299V     2.648V
249.2ns   2.168V     1.379V     2.649V
[Falling Waveform]
R_fixture= 50.000000
V_fixture= 3.300000
V_fixture_min= 2.700000
V_fixture_max= 3.600000
|time   V(typ)   V(min)   V(max)
0s        3.3V       2.7V       3.6V
3.003ns   3.3V       2.7V       3.593V
5.506ns   3.274V     2.7V       3.425V
14.51ns   2.803V     2.65V      2.335V
21.02ns   2.401V     2.56V      1.767V
29.53ns   1.999V     2.389V     1.31V
39.54ns   1.674V     2.195V     1.116V
60.56ns   1.365V     1.89V      1.045V
88.09ns   1.29V      1.683V     1.032V
249.2ns   1.277V     1.572V     1.031V
[Falling Waveform]
R_fixture= 50.000000
V_fixture= 0.0
V_fixture_min= 0.0
V_fixture_max= 0.0
|time   V(typ)   V(min)   V(max)
0s        2.168V     1.379V     2.649V
400.4ps   2.157V     1.383V     2.529V
540.5ps   1.955V     1.386V     1.776V
700.7ps   1.253V     1.343V     610.1mV
800.8ps   758.3mV    1.242V     167.3mV
940.9ps   288.3mV    1.008V     29.53mV
1.101ns   31.61mV    655.2mV    9.378mV
1.502ns   3.45mV     57.56mV    3.563mV
1.902ns   1.918mV    -13.33mV   3.48mV
9.97ns    1.014mV    1.116mV    973.4uV
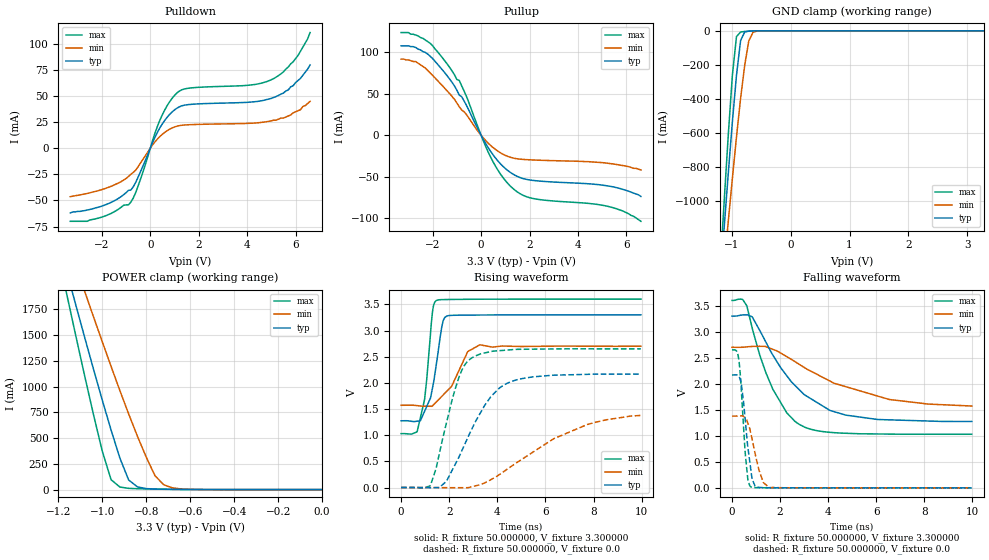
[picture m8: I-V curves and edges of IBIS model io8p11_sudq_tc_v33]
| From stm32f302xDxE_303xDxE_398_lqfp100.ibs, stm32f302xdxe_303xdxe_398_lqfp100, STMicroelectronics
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|   Model io8p11_sudq_tc_v33
[Model]  io8p11_sudq_tc_v33
Model_type I/O
Polarity   Non-Inverting
Enable   Active-Low
Vinl =   0.990000V
Vinh =   2.310000V
Vmeas =  1.650000V
Cref =   30.000000pF
Rref =   100.000000M
Vref =   0.0V
C_comp   1.325200pF   1.251200pF   1.426700pF
[Temperature Range]   25.000000   0.125000k   -40.000000
[Pullup Reference]   3.300000V   2.700000V   3.600000V
[Pulldown Reference]   0.0V   0.0V   0.0V
[POWER Clamp Reference]   3.300000V   2.700000V   3.600000V
[GND Clamp Reference]   0.0V   0.0V   0.0V
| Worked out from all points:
|   slope of the pulldown table from 0 to 0.495 V, typ, clamps not added: 21.3 ohm
|   slope of the pullup table from 0 to 0.495 V, typ, clamps not added: 20.9 ohm
|   GND clamp passes 1 mA (typ) near -0.67 V on its own axis
|   POWER clamp passes 1 mA (typ) near -0.60 V on its own axis
|   rising waveform, R_fixture 50.000000, V_fixture 3.300000: 20-80 % time 440ps typ, 838ps min, 340ps max; typ from 1.27 V to 3.3 V
|   rising waveform, R_fixture 50.000000, V_fixture 0.0: 20-80 % time 1.49ns typ, 3.04ns min, 882ps max; typ from 0 V to 2.17 V
|   falling waveform, R_fixture 50.000000, V_fixture 3.300000: 20-80 % time 2.09ns typ, 3.36ns min, 1.32ns max; typ from 3.3 V to 1.27 V
|   falling waveform, R_fixture 50.000000, V_fixture 0.0: 20-80 % time 301ps typ, 416ps min, 224ps max; typ from 2.17 V to 0 V
[Pulldown]
|Voltage   I(typ)   I(min)   I(max)
-3.3V     -62mA      -46.4mA    -70mA
-2V       -55.5mA    -39.6mA    -66mA
-800mV    -40.04mA   -24.89mA   -51.58mA
-500mV    -27.57mA   -17.6mA    -36.07mA
400mV     19.71mA    11.36mA    27.01mA
700mV     29.83mA    16.93mA    40.97mA
1.1V      38.46mA    21.2mA     53.02mA
1.6V      41.98mA    22.62mA    57.7mA
4.1V      44.26mA    24mA       60.59mA
5V        47.9mA     26.3mA     65.8mA
5.9V      60mA       34mA       83mA
6.6V      80mA       45mA       111mA
[Pullup]
|Voltage   I(typ)   I(min)   I(max)
-3.3V     108mA      92mA       124mA
-2.7V     106mA      89mA       121mA
-2.2V     98mA       78.2mA     113mA
-1.4V     71.8mA     53.5mA     86.1mA
-900mV    48.51mA    34.23mA    66.14mA
-700mV    41.33mA    28.36mA    53.31mA
400mV     -19.77mA   -12.52mA   -26.8mA
900mV     -37.48mA   -22.89mA   -50.99mA
1.4V      -48.39mA   -28.06mA   -66.43mA
2.2V      -54.79mA   -29.98mA   -76.75mA
5.3V      -61.6mA    -34.2mA    -86.4mA
6.6V      -74mA      -42mA      -104mA
[GND_clamp]
|Voltage   I(typ)   I(min)   I(max)
-3.3V     -9.739A    -9.975A    -9.587A
-1.2V     -1.489A    -1.65A     -1.416A
-1.13V    -1.162A    -1.385A    -1.009A
-1.06V    -842.2mA   -1.125A    -616.9mA
-990mV    -537.1mA   -870.1mA   -263mA
-920mV    -262.4mA   -625.3mA   -33.96mA
-850mV    -56.94mA   -397.4mA   -7.08mA
-780mV    -7.011mA   -202.2mA   -3.71mA
-710mV    -1.778mA   -58.23mA   -1.736mA
-640mV    -550uA     -8.783mA   -542.4uA
-570mV    -109.8uA   -1.292mA   -86.89uA
3.28V     0A         0A         0A
[POWER_clamp]
|Voltage   I(typ)   I(min)   I(max)
-3.28V    9.897A     9.838A     9.594A
-1.16V    2.103A     2.419A     1.88A
-1.12V    1.788A     2.17A      1.488A
-1.08V    1.476A     1.923A     1.102A
-1V       868.1mA    1.435A     373.1mA
-960mV    578.2mA    1.196A     96.06mA
-880mV    93.24mA    734.1mA    12.01mA
-840mV    26.3mA     517.4mA    8.56mA
-760mV    5.106mA    134mA      5.119mA
-720mV    3.355mA    46.34mA    3.808mA
-600mV    1.005mA    2.564mA    1.072mA
0V        0A         0A         0A
[Ramp]
| variable   typ   min   max
dV/dt_r  1.30026/1.48750n   0.78774/3.04457n   1.58868/0.88064n
dV/dt_f  1.21512/2.09120n   0.66090/3.37878n   1.54254/1.31444n
R_load = 50.000000
[Rising Waveform]
R_fixture= 50.000000
V_fixture= 3.300000
V_fixture_min= 2.700000
V_fixture_max= 3.600000
|time   V(typ)   V(min)   V(max)
0s        1.275V     1.571V     1.03V
680.7ps   1.268V     1.564V     1.098V
981ps     1.463V     1.553V     1.707V
1.301ns   1.896V     1.559V     3.349V
1.461ns   2.35V      1.634V     3.573V
1.742ns   3.177V     1.767V     3.591V
1.942ns   3.282V     1.861V     3.592V
2.763ns   3.294V     2.591V     3.596V
3.263ns   3.296V     2.724V     3.598V
9.97ns    3.3V       2.7V       3.6V
[Rising Waveform]
R_fixture= 50.000000
V_fixture= 0.0
V_fixture_min= 0.0
V_fixture_max= 0.0
|time   V(typ)   V(min)   V(max)
0s        -14.38uV   -16.71uV   -16.86uV
1.221ns   -4.577mV   -179uV     42.71mV
1.461ns   -2.146mV   -967.6uV   383.1mV
1.882ns   117.7mV    -2.713mV   1.231V
2.402ns   580.9mV    -3.427mV   2.103V
2.963ns   1.14V      17.7mV     2.483V
3.724ns   1.733V     148.3mV    2.596V
4.665ns   2.038V     431.4mV    2.635V
7.728ns   2.162V     1.202V     2.65V
9.97ns    2.167V     1.378V     2.649V
[Falling Waveform]
R_fixture= 50.000000
V_fixture= 3.300000
V_fixture_min= 2.700000
V_fixture_max= 3.600000
|time   V(typ)   V(min)   V(max)
0s        3.3V       2.7V       3.6V
600.6ps   3.324V     2.707V     3.508V
840.8ps   3.285V     2.716V     3.069V
1.161ns   3.018V     2.719V     2.542V
1.702ns   2.549V     2.66V      1.891V
2.282ns   2.151V     2.519V     1.439V
2.803ns   1.883V     2.371V     1.218V
4.745ns   1.396V     1.942V     1.048V
6.547ns   1.306V     1.697V     1.033V
9.97ns    1.275V     1.571V     1.03V
[Falling Waveform]
R_fixture= 50.000000
V_fixture= 0.0
V_fixture_min= 0.0
V_fixture_max= 0.0
|time   V(typ)   V(min)   V(max)
0s        2.167V     1.378V     2.649V
280.3ps   2.146V     1.382V     2.47V
400.4ps   1.955V     1.384V     1.786V
560.6ps   1.259V     1.341V     615mV
660.7ps   777.7mV    1.241V     157.8mV
800.8ps   288.6mV    1.011V     15.37mV
961ps     31.52mV    662.3mV    4.349mV
1.121ns   10.04mV    342.7mV    2.465mV
1.562ns   2.208mV    4.875mV    1.389mV
9.97ns    -14.38uV   -16.71uV   -16.86uV
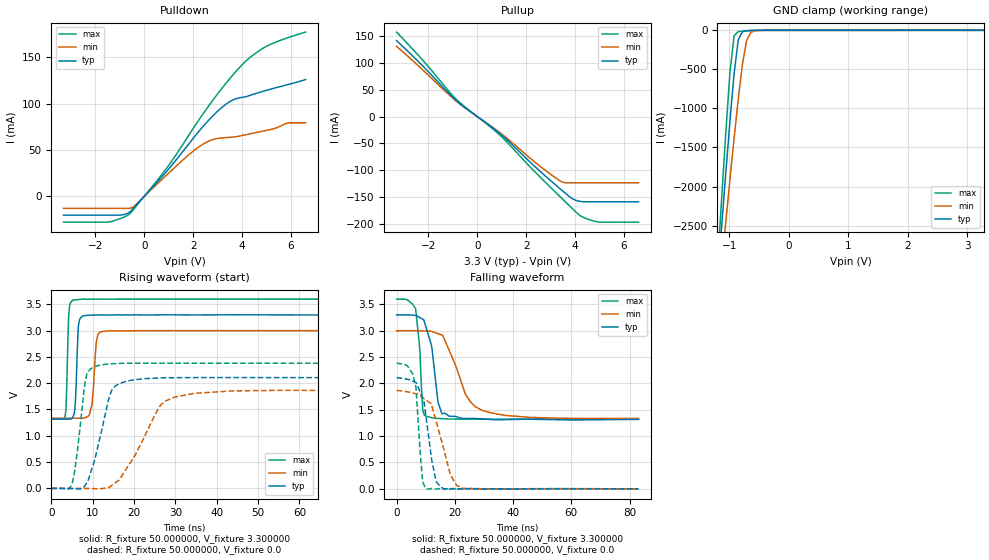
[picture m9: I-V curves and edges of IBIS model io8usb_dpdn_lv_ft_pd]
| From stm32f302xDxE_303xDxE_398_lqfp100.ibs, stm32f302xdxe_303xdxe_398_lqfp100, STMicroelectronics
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|   Model io8usb_dpdn_lv_ft_pd
[Model]  io8usb_dpdn_lv_ft_pd
Model_type I/O
Polarity   Non-Inverting
Enable   Active-Low
Vinl =   0.990000V
Vinh =   2.310000V
Vmeas =  1.650000V
Cref =   50.000000pF
Rref =   100.000000M
Vref =   0.0V
C_comp   5.029800pF   4.851400pF   5.238000pF
[Temperature Range]   25.000000   0.125000k   -40.000000
[Pullup Reference]   3.300000V   3.000000V   3.600000V
[Pulldown Reference]   0.0V   0.0V   0.0V
[POWER Clamp Reference]   3.300000V   3.000000V   3.600000V
[GND Clamp Reference]   0.0V   0.0V   0.0V
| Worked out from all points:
|   slope of the pulldown table from 0 to 0.495 V, typ, clamps not added: 34.5 ohm
|   slope of the pullup table from 0 to 0.495 V, typ, clamps not added: 30.3 ohm
|   GND clamp passes 1 mA (typ) near -0.59 V on its own axis
|   rising waveform, R_fixture 50.000000, V_fixture 3.300000: 20-80 % time 564ps typ, 846ps min, 474ps max; typ from 1.32 V to 3.3 V
|   rising waveform, R_fixture 50.000000, V_fixture 0.0: 20-80 % time 3.84ns typ, 7.53ns min, 2.08ns max; typ from 0 V to 2.11 V
|   falling waveform, R_fixture 50.000000, V_fixture 3.300000: 20-80 % time 3.08ns typ, 7.43ns min, 1.63ns max; typ from 3.3 V to 1.32 V
|   falling waveform, R_fixture 50.000000, V_fixture 0.0: 20-80 % time 3.23ns typ, 5.44ns min, 1.75ns max; typ from 2.11 V to 0 V
[Pulldown]
|Voltage   I(typ)   I(min)   I(max)
-3.3V     -20.2mA    -12.85mA   -27.8mA
-1.4V     -20.2mA    -12.85mA   -27.4mA
-600mV    -16.97mA   -12.85mA   -19mA
-400mV    -11.64mA   -10.26mA   -12.92mA
900mV     26.39mA    22.6mA     29.76mA
2.1V      65.72mA    50.72mA    77.05mA
2.7V      83.87mA    60.29mA    99.79mA
3.3V      98.46mA    63.32mA    120.5mA
4.1V      107.1mA    66.16mA    144.4mA
4.8V      112.8mA    70.03mA    158.7mA
5.9V      120.7mA    79.32mA    171.3mA
6.6V      126mA      79.32mA    177.1mA
[Pullup]
|Voltage   I(typ)   I(min)   I(max)
-3.3V     140.7mA    130.2mA    156.5mA
-2.2V     92.45mA    85.22mA    102.9mA
-900mV    31.27mA    30.18mA    33.72mA
1V        -34.43mA   -32.42mA   -37.73mA
2.5V      -98.62mA   -89.74mA   -108.9mA
3.4V      -134.4mA   -119.6mA   -149.1mA
3.6V      -142mA     -122.8mA   -157.9mA
4V        -154.8mA   -122.8mA   -175.4mA
4.2V      -157.3mA   -122.8mA   -183.4mA
4.6V      -158.1mA   -122.8mA   -191.5mA
5V        -158.1mA   -122.8mA   -195.7mA
6.6V      -158.1mA   -122.8mA   -195.9mA
[GND_clamp]
|Voltage   I(typ)   I(min)   I(max)
-3.3V     -9.706A    -9.44A     -9.292A
-1.2V     -3.211A    -3.572A    -3.02A
-1.13V    -2.511A    -3.009A    -2.153A
-1.06V    -1.824A    -2.453A    -1.311A
-990mV    -1.16A     -1.907A    -534mA
-920mV    -548mA     -1.377A    -70.1mA
-850mV    -120.5mA   -876.3mA   -15.92mA
-780mV    -17.67mA   -431.2mA   -9.208mA
-710mV    -5.454mA   -131mA     -5.036mA
-640mV    -2.091mA   -25.75mA   -2.018mA
-570mV    -553.8uA   -6.328mA   -449uA
3.28V     83.63uA    70.53uA    93.37uA
[POWER_clamp]
|Voltage   I(typ)   I(min)   I(max)
-3.28V    0A         0A         0A
0V        0A         0A         0A
[Ramp]
| variable   typ   min   max
dV/dt_r  1.26372/3.83269n   1.11798/7.51677n   1.42764/2.07808n
dV/dt_f  1.18404/3.07451n   0.99900/7.43277n   1.36638/1.63282n
R_load = 50.000000
[Rising Waveform]
R_fixture= 50.000000
V_fixture= 3.300000
V_fixture_min= 3.000000
V_fixture_max= 3.600000
|time   V(typ)   V(min)   V(max)
0s        1.317V     1.334V     1.321V
3.337ns   1.317V     1.334V     1.389V
4.171ns   1.317V     1.334V     3.252V
5.172ns   1.35V      1.334V     3.579V
5.839ns   1.707V     1.334V     3.584V
6.507ns   3.078V     1.334V     3.59V
7.674ns   3.28V      1.333V     3.598V
9.843ns   3.293V     1.613V     3.596V
11.85ns   3.295V     2.974V     3.597V
83.08ns   3.298V     2.999V     3.598V
[Rising Waveform]
R_fixture= 50.000000
V_fixture= 0.0
V_fixture_min= 0.0
V_fixture_max= 0.0
|time   V(typ)   V(min)   V(max)
0s        24.73nV    326.3nV    86.75nV
5.005ns   -2.526mV   3.559uV    84.48mV
6.173ns   -9.31mV    6.6uV      642mV
8.175ns   56.83mV    -637.2uV   2.033V
11.01ns   721.1mV    -8.304mV   2.328V
13.85ns   1.693V     16.32mV    2.365V
15.52ns   1.951V     110.4mV    2.372V
26.03ns   2.099V     1.538V     2.38V
29.86ns   2.104V     1.735V     2.38V
83.08ns   2.106V     1.863V     2.38V
[Falling Waveform]
R_fixture= 50.000000
V_fixture= 3.300000
V_fixture_min= 3.000000
V_fixture_max= 3.600000
|time   V(typ)   V(min)   V(max)
0s        3.298V     2.999V     3.598V
6.507ns   3.288V     2.999V     3.42V
8.008ns   3.248V     2.997V     2.615V
9.009ns   3.217V     2.995V     1.494V
10.01ns   3.086V     2.993V     1.381V
12.01ns   2.715V     2.987V     1.351V
15.68ns   1.422V     2.914V     1.33V
23.69ns   1.336V     1.791V     1.321V
29.36ns   1.326V     1.489V     1.321V
83.08ns   1.317V     1.334V     1.321V
[Falling Waveform]
R_fixture= 50.000000
V_fixture= 0.0
V_fixture_min= 0.0
V_fixture_max= 0.0
|time   V(typ)   V(min)   V(max)
0s        2.106V     1.863V     2.38V
3.67ns    2.079V     1.84V      2.336V
6.507ns   2.018V     1.806V     1.966V
8.842ns   1.744V     1.733V     198.9mV
10.51ns   1.2V       1.669V     -1.799mV
12.01ns   567.1mV    1.596V     7.106mV
13.68ns   131mV      1.264V     -3.06mV
18.52ns   -1.918mV   264.4mV    5.492mV
22.86ns   -739uV     9.687mV    880.4uV
83.08ns   24.73nV    326.3nV    86.75nV
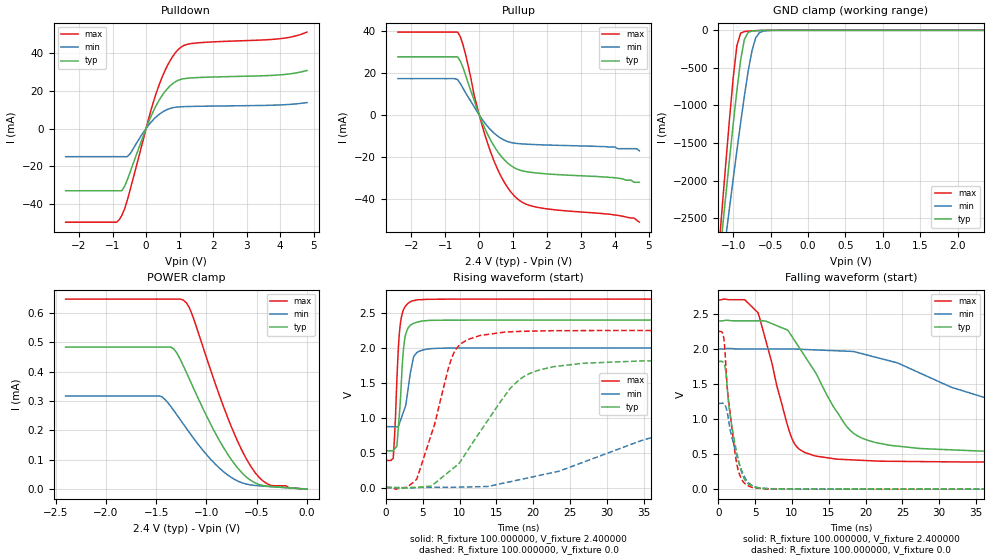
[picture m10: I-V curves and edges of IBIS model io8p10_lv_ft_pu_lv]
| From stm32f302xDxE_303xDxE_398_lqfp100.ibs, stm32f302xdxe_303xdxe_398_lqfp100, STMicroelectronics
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|   Model io8p10_lv_ft_pu_lv
[Model]  io8p10_lv_ft_pu_lv
Model_type I/O
Polarity   Non-Inverting
Enable   Active-Low
Vinl =   0.720000V
Vinh =   1.680000V
Vmeas =  1.200000V
Cref =   50.000000pF
Rref =   100.000000M
Vref =   0.0V
C_comp   5.024800pF   4.846300pF   5.260300pF
[Temperature Range]   25.000000   0.125000k   -40.000000
[Pullup Reference]   2.400000V   2.000000V   2.700000V
[Pulldown Reference]   0.0V   0.0V   0.0V
[POWER Clamp Reference]   2.400000V   2.000000V   2.700000V
[GND Clamp Reference]   0.0V   0.0V   0.0V
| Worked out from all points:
|   slope of the pulldown table from 0 to 0.36 V, typ, clamps not added: 25.5 ohm
|   slope of the pullup table from 0 to 0.36 V, typ, clamps not added: 28.4 ohm
|   GND clamp passes 1 mA (typ) near -0.60 V on its own axis
|   rising waveform, R_fixture 100.000000, V_fixture 2.400000: 20-80 % time 713ps typ, 1.14ns min, 629ps max; typ from 0.527 V to 2.4 V
|   rising waveform, R_fixture 100.000000, V_fixture 0.0: 20-80 % time 7.16ns typ, 20.9ns min, 3.54ns max; typ from 0.001 V to 1.82 V
|   falling waveform, R_fixture 100.000000, V_fixture 2.400000: 20-80 % time 6.43ns typ, 17.7ns min, 3.43ns max; typ from 2.4 V to 0.527 V
|   falling waveform, R_fixture 100.000000, V_fixture 0.0: 20-80 % time 1.63ns typ, 1.85ns min, 1.36ns max; typ from 1.82 V to 0.001 V
[Pulldown]
|Voltage   I(typ)   I(min)   I(max)
-2.4V     -33.16mA   -14.98mA   -49.86mA
-880mV    -33.16mA   -14.98mA   -49.86mA
-800mV    -33.16mA   -14.98mA   -48.55mA
-640mV    -30.75mA   -14.98mA   -42.77mA
-480mV    -23.43mA   -13.57mA   -32.92mA
80mV      3.651mA    1.905mA    5.506mA
400mV     15.37mA    7.665mA    23.73mA
720mV     22.75mA    10.69mA    36.23mA
1.04V     26.18mA    11.57mA    43.27mA
1.52V     27.09mA    11.81mA    45.55mA
4V        28.55mA    12.55mA    47.81mA
4.8V      30.9mA     13.81mA    51.31mA
[Pullup]
|Voltage   I(typ)   I(min)   I(max)
-2.4V     27.74mA    17.36mA    39.51mA
-640mV    27.74mA    16.89mA    39.51mA
-480mV    22.59mA    12.74mA    33.43mA
-80mV     3.427mA    2.072mA    4.957mA
160mV     -6.219mA   -3.714mA   -9.136mA
320mV     -11.51mA   -6.781mA   -16.98mA
720mV     -21mA      -11.8mA    -31.53mA
1.12V     -25.77mA   -13.54mA   -39.82mA
1.76V     -27.69mA   -14.12mA   -44.06mA
4.08V     -30mA      -16mA      -47.7mA
4.56V     -32mA      -16mA      -49mA
4.72V     -32mA      -17mA      -51mA
[GND_clamp]
|Voltage   I(typ)   I(min)   I(max)
-2.4V     -9.914A    -9.862A    -9.419A
-1.2V     -3.21A     -3.567A    -3.02A
-1.15V    -2.709A    -3.165A    -2.399A
-1.1V     -2.213A    -2.766A    -1.788A
-1.05V    -1.726A    -2.371A    -1.195A
-950mV    -800.5mA   -1.599A    -202.1mA
-900mV    -394.9mA   -1.228A    -38.17mA
-850mV    -120.2mA   -874.5mA   -15.91mA
-750mV    -9.807mA   -279.4mA   -7.273mA
-700mV    -4.736mA   -102mA     -4.51mA
-600mV    -1.032mA   -11.09mA   -922.6uA
2.35V     0A         0A         0A
[POWER_clamp]
|Voltage   I(typ)   I(min)   I(max)
-2.4V     483.6uA    317.4uA    647uA
-1.47V    483.6uA    317.4uA    647uA
-1.32V    475.8uA    265.5uA    647uA
-1.23V    420.2uA    221.9uA    643.4uA
-1.17V    375.2uA    193uA      618uA
-1.14V    352.5uA    178.9uA    592.4uA
-840mV    147.3uA    62.31uA    290.1uA
-690mV    72.45uA    27.83uA    163.1uA
-540mV    25.83uA    13.54uA    67.87uA
-450mV    13.39uA    10.74uA    31.49uA
-360mV    9.215uA    8.523uA    13uA
0V        0A         0A         0A
[Ramp]
| variable   typ   min   max
dV/dt_r  1.09275/7.14890n   0.73281/20.92082n   1.34926/3.53823n
dV/dt_f  1.12405/6.42050n   0.67481/17.66092n   1.38688/3.42334n
R_load = 100.000000
[Rising Waveform]
R_fixture= 100.000000
V_fixture= 2.400000
V_fixture_min= 2.000000
V_fixture_max= 2.700000
|time   V(typ)   V(min)   V(max)
0s        526.5mV    872.5mV    388.6mV
1.001ns   532.8mV    871.4mV    420.7mV
1.301ns   568.6mV    870.1mV    999.5mV
1.502ns   597mV      869.5mV    1.563V
1.902ns   1.142V     937.6mV    2.286V
2.503ns   2.088V     1.118V     2.572V
3.504ns   2.338V     1.738V     2.671V
4.204ns   2.368V     1.933V     2.688V
6.507ns   2.396V     1.992V     2.697V
49.85ns   2.4V       2V         2.7V
[Rising Waveform]
R_fixture= 100.000000
V_fixture= 0.0
V_fixture_min= 0.0
V_fixture_max= 0.0
|time   V(typ)   V(min)   V(max)
0s        1.055mV    1.354mV    939.9uV
2.803ns   -2.16mV    -3.419mV   2.465mV
4.204ns   3.54mV     123.7uV    124.2mV
6.206ns   24.76mV    3.956mV    773.8mV
9.209ns   282.7mV    4.63mV     1.925V
12.81ns   804.1mV    13.63mV    2.179V
18.42ns   1.569V     119.4mV    2.238V
26.63ns   1.779V     357.5mV    2.248V
51.45ns   1.823V     1.102V     2.25V
99.7ns    1.822V     1.224V     2.25V
[Falling Waveform]
R_fixture= 100.000000
V_fixture= 2.400000
V_fixture_min= 2.000000
V_fixture_max= 2.700000
|time   V(typ)   V(min)   V(max)
0s        2.4V       2V         2.7V
3.604ns   2.401V     2.001V     2.702V
5.405ns   2.402V     2V         2.517V
10.01ns   2.179V     2V         723.2mV
13.21ns   1.663V     1.987V     473.6mV
17.82ns   850.5mV    1.967V     420.3mV
23.42ns   624.8mV    1.826V     398.5mV
43.24ns   536.6mV    1.077V     388.7mV
50.05ns   529.4mV    970.8mV    388.5mV
99.7ns    526.5mV    872.5mV    388.6mV
[Falling Waveform]
R_fixture= 100.000000
V_fixture= 0.0
V_fixture_min= 0.0
V_fixture_max= 0.0
|time   V(typ)   V(min)   V(max)
0s        1.822V     1.224V     2.25V
800.8ps   1.792V     1.219V     2.127V
1.101ns   1.606V     1.154V     1.648V
1.301ns   1.353V     1.055V     1.363V
1.702ns   1.001V     810.7mV    1.015V
2.503ns   533.3mV    484.7mV    371.7mV
3.203ns   232.3mV    264.4mV    138.5mV
3.904ns   94mV       118.9mV    55.49mV
7.107ns   7.025mV    7.417mV    4.723mV
49.85ns   1.055mV    1.354mV    939.9uV
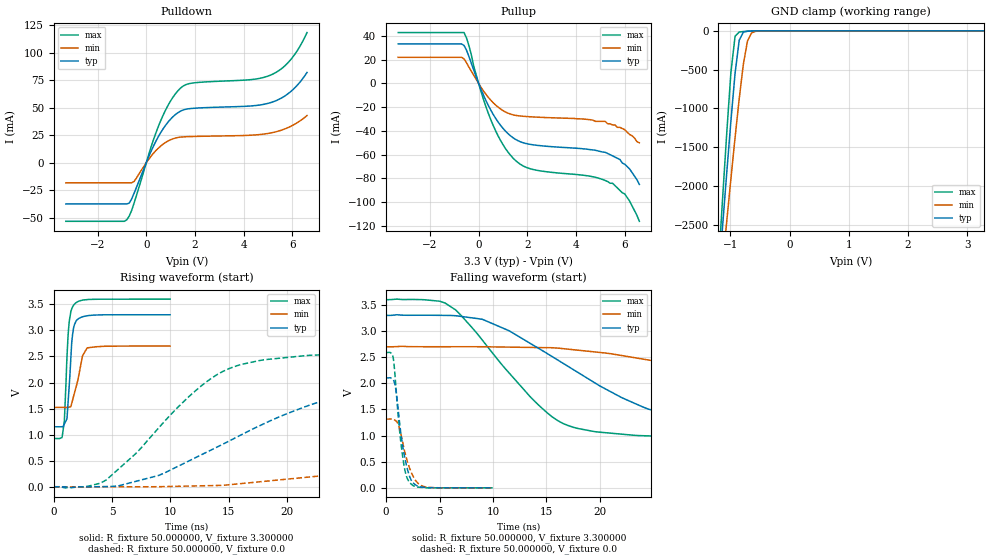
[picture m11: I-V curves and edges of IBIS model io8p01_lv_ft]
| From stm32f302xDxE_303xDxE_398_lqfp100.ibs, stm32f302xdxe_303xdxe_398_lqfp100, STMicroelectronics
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|   Model io8p01_lv_ft
[Model]  io8p01_lv_ft
Model_type I/O
Polarity   Non-Inverting
Enable   Active-Low
Vinl =   0.990000V
Vinh =   2.310000V
Vmeas =  1.650000V
Cref =   50.000000pF
Rref =   100.000000M
Vref =   0.0V
C_comp   5.028100pF   4.857200pF   5.254400pF
[Temperature Range]   25.000000   0.125000k   -40.000000
[Pullup Reference]   3.300000V   2.700000V   3.600000V
[Pulldown Reference]   0.0V   0.0V   0.0V
[POWER Clamp Reference]   3.300000V   2.700000V   3.600000V
[GND Clamp Reference]   0.0V   0.0V   0.0V
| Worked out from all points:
|   slope of the pulldown table from 0 to 0.495 V, typ, clamps not added: 20.9 ohm
|   slope of the pullup table from 0 to 0.495 V, typ, clamps not added: 22.2 ohm
|   GND clamp passes 1 mA (typ) near -0.59 V on its own axis
|   rising waveform, R_fixture 50.000000, V_fixture 3.300000: 20-80 % time 373ps typ, 696ps min, 339ps max; typ from 1.15 V to 3.3 V
|   rising waveform, R_fixture 50.000000, V_fixture 0.0: 20-80 % time 12.7ns typ, 30.6ns min, 7.02ns max; typ from 0 V to 2.1 V
|   falling waveform, R_fixture 50.000000, V_fixture 3.300000: 20-80 % time 11ns typ, 22.7ns min, 6.89ns max; typ from 3.3 V to 1.15 V
|   falling waveform, R_fixture 50.000000, V_fixture 0.0: 20-80 % time 883ps typ, 1.07ns min, 741ps max; typ from 2.1 V to 0 V
[Pulldown]
|Voltage   I(typ)   I(min)   I(max)
-3.3V     -37.45mA   -18.2mA    -53.24mA
-800mV    -37.45mA   -18.2mA    -51.9mA
-700mV    -36.7mA    -18.2mA    -48.48mA
-500mV    -27.71mA   -17.01mA   -36.66mA
200mV     10.57mA    6.084mA    14.57mA
500mV     23.91mA    13.38mA    33.24mA
900mV     37.17mA    19.87mA    52.48mA
1.3V      45.55mA    23.01mA    65.5mA
1.8V      49.29mA    23.83mA    72.18mA
5.1V      54.68mA    27.07mA    79.72mA
5.9V      64.2mA     32.82mA    93.01mA
6.6V      82.13mA    42.97mA    118.4mA
[Pullup]
|Voltage   I(typ)   I(min)   I(max)
-3.3V     33.16mA    21.89mA    42.7mA
-600mV    31.87mA    20.58mA    42.7mA
-400mV    22.79mA    13.76mA    31.9mA
100mV     -5.13mA    -3.299mA   -6.952mA
500mV     -22.5mA    -14.16mA   -30.52mA
900mV     -35.28mA   -21.55mA   -48mA
1.4V      -45.54mA   -26.4mA    -62.53mA
2.2V      -51.57mA   -28.22mA   -72.25mA
4.7V      -56mA      -31mA      -78.6mA
5.5V      -61mA      -35mA      -84mA
6V        -68mA      -39mA      -93mA
6.6V      -85mA      -50mA      -116mA
[GND_clamp]
|Voltage   I(typ)   I(min)   I(max)
-3.3V     -9.706A    -9.438A    -9.292A
-1.2V     -3.211A    -3.571A    -3.02A
-1.13V    -2.511A    -3.008A    -2.153A
-1.06V    -1.824A    -2.453A    -1.311A
-990mV    -1.16A     -1.907A    -534mA
-920mV    -548mA     -1.377A    -70.08mA
-850mV    -120.4mA   -875.9mA   -15.9mA
-780mV    -17.66mA   -430.9mA   -9.191mA
-710mV    -5.44mA    -130.8mA   -5.02mA
-640mV    -2.077mA   -25.65mA   -2.003mA
-570mV    -540.4uA   -6.293mA   -433.9uA
3.28V     0A         0A         0A
[POWER_clamp]
|Voltage   I(typ)   I(min)   I(max)
-3.28V    0A         0A         0A
0V        0A         0A         0A
[Ramp]
| variable   typ   min   max
dV/dt_r  1.26216/12.63911n   0.78954/30.59920n   1.55454/7.01494n
dV/dt_f  1.28958/11.02992n   0.70722/22.79612n   1.60472/6.88121n
R_load = 50.000000
[Rising Waveform]
R_fixture= 50.000000
V_fixture= 3.300000
V_fixture_min= 2.700000
V_fixture_max= 3.600000
|time   V(typ)   V(min)   V(max)
0s        1.151V     1.522V     925.5mV
720.7ps   1.152V     1.522V     965.2mV
900.9ps   1.204V     1.521V     1.253V
1.121ns   1.3V       1.522V     2.454V
1.341ns   2.01V      1.53V      3.2V
1.542ns   2.785V     1.606V     3.416V
1.742ns   3.087V     1.775V     3.496V
2.462ns   3.26V      2.513V     3.581V
2.863ns   3.281V     2.665V     3.591V
9.97ns    3.3V       2.7V       3.6V
[Rising Waveform]
R_fixture= 50.000000
V_fixture= 0.0
V_fixture_min= 0.0
V_fixture_max= 0.0
|time   V(typ)   V(min)   V(max)
0s        6.163nV    51.64nV    9.065nV
4.505ns   4.706mV    -221.5uV   132.3mV
9.009ns   218.5mV    1.524mV    1.134V
14.51ns   819.2mV    27.28mV    2.215V
22.02ns   1.573V     189.8mV    2.523V
28.53ns   1.91V      354mV      2.572V
38.54ns   2.053V     651mV      2.589V
58.06ns   2.098V     1.085V     2.591V
78.58ns   2.105V     1.254V     2.591V
249.2ns   2.104V     1.316V     2.591V
[Falling Waveform]
R_fixture= 50.000000
V_fixture= 3.300000
V_fixture_min= 2.700000
V_fixture_max= 3.600000
|time   V(typ)   V(min)   V(max)
0s        3.3V       2.7V       3.6V
5.506ns   3.301V     2.701V     3.538V
9.009ns   3.225V     2.7V       2.825V
13.51ns   2.762V     2.687V     1.736V
16.02ns   2.452V     2.675V     1.292V
23.52ns   1.593V     2.482V     1.002V
30.03ns   1.319V     2.25V      958mV
45.55ns   1.189V     1.773V     930.5mV
74.07ns   1.156V     1.572V     925.7mV
249.2ns   1.151V     1.522V     925.5mV
[Falling Waveform]
R_fixture= 50.000000
V_fixture= 0.0
V_fixture_min= 0.0
V_fixture_max= 0.0
|time   V(typ)   V(min)   V(max)
0s        2.104V     1.316V     2.591V
660.7ps   2.069V     1.315V     2.487V
900.9ps   1.888V     1.283V     1.967V
1.161ns   1.431V     1.19V      1.296V
1.481ns   887.1mV    934.5mV    692.9mV
1.822ns   499.7mV    626.8mV    279.7mV
2.222ns   204.2mV    361.2mV    94.97mV
2.783ns   52.61mV    132.3mV    24.03mV
3.684ns   7.273mV    18.78mV    2.195mV
9.97ns    6.163nV    51.64nV    9.065nV
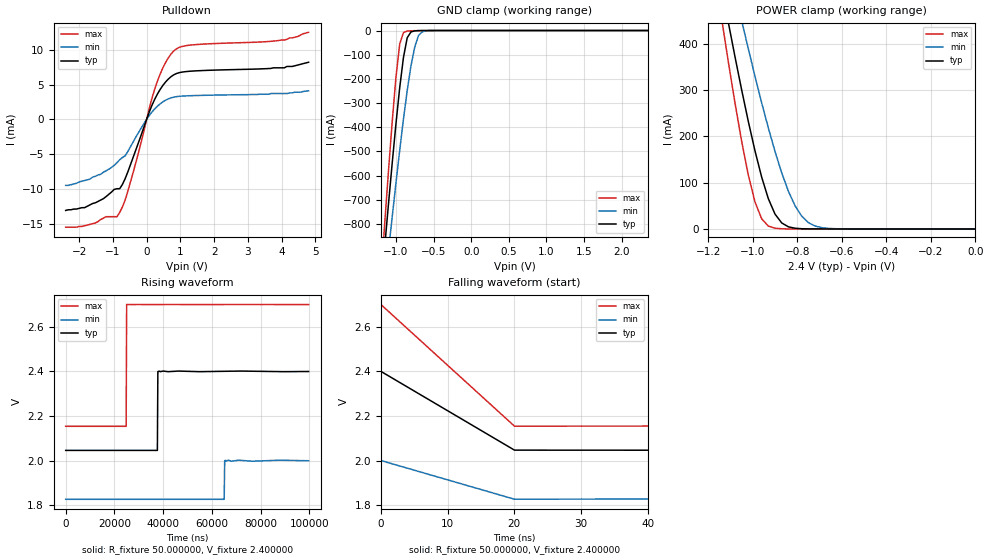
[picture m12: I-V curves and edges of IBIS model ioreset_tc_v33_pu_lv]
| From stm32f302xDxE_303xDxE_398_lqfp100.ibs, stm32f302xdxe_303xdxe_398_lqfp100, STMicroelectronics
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|   Model ioreset_tc_v33_pu_lv
[Model]  ioreset_tc_v33_pu_lv
Model_type I/O_open_drain
Polarity   Inverting
Enable   Active-High
Vinl =   0.720000V
Vinh =   1.680000V
Vmeas =  1.200000V
Cref =   1.0000000000000001E-7F
Rref =   1.000000k
Vref =   2.400000V
C_comp   1.015800pF   0.956670pF   1.089900pF
[Temperature Range]   25.000000   0.125000k   -40.000000
[Pullup Reference]   2.400000V   2.000000V   2.700000V
[Pulldown Reference]   0.0V   0.0V   0.0V
[POWER Clamp Reference]   2.400000V   2.000000V   2.700000V
[GND Clamp Reference]   0.0V   0.0V   0.0V
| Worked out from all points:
|   slope of the pulldown table from 0 to 0.36 V, typ, clamps not added: 90.8 ohm
|   GND clamp passes 1 mA (typ) near -0.73 V on its own axis
|   POWER clamp passes 1 mA (typ) near -0.79 V on its own axis
|   rising waveform, R_fixture 50.000000, V_fixture 2.400000: 20-80 % time 120ns typ, 119ns min, 120ns max; typ from 2.05 V to 2.4 V
|   falling waveform, R_fixture 50.000000, V_fixture 2.400000: 20-80 % time 12ns typ, 12ns min, 12ns max; typ from 2.4 V to 2.05 V
[Pulldown]
|Voltage   I(typ)   I(min)   I(max)
-2.4V     -13.1mA    -9.5mA     -15.5mA
-1.92V    -12.7mA    -8.9mA     -15.4mA
-1.36V    -11.6mA    -7.9mA     -14.4mA
-880mV    -9.976mA   -6.23mA    -14mA
-800mV    -9.976mA   -5.82mA    -13.4mA
-560mV    -7.592mA   -4.653mA   -10.39mA
80mV      1.078mA    566.3uA    1.62mA
320mV     3.637mA    1.891mA    5.489mA
560mV     5.357mA    2.738mA    8.148mA
880mV     6.571mA    3.252mA    10.12mA
4.08V     7.4mA      3.7mA      11.4mA
4.8V      8.2mA      4.1mA      12.5mA
[GND_clamp]
|Voltage   I(typ)   I(min)   I(max)
-2.4V     -5.625A    -4.928A    -6.726A
-1.2V     -1.076A    -1.208A    -1.024A
-1.15V    -896.6mA   -1.061A    -801.3mA
-1.1V     -720.7mA   -914.8mA   -584.7mA
-1.05V    -549.7mA   -771.3mA   -378.8mA
-1V       -386.4mA   -631.1mA   -194.3mA
-950mV    -236.6mA   -495.4mA   -55.51mA
-900mV    -111.3mA   -366.4mA   -8.598mA
-850mV    -29.69mA   -247.7mA   -2.329mA
-750mV    -1.386mA   -67.71mA   -789.5uA
-650mV    -196.3uA   -5.367mA   -189.3uA
2.35V     0A         0A         0A
[POWER_clamp]
|Voltage   I(typ)   I(min)   I(max)
-2.4V     4.072A     3.583A     4.91A
-1.14V    522.8mA    640.7mA    454.7mA
-1.11V    446.7mA    576.2mA    361.6mA
-1.05V    300.6mA    450.2mA    189.7mA
-1.02V    232.3mA    389.1mA    116.3mA
-990mV    168.6mA    329.7mA    58.23mA
-960mV    111.9mA    272.5mA    21.88mA
-900mV    31.99mA    167.1mA    1.551mA
-810mV    1.537mA    49.91mA    26.39uA
-750mV    162.7uA    13.67mA    6.413uA
-630mV    4.305uA    515.2uA    2.845uA
0V        0A         0A         0A
[Ramp]
| variable   typ   min   max
dV/dt_r  0.21306/60.00000n   0.10242/58.86207n   0.32724/59.95603n
dV/dt_f  0.21234/60.05090n   0.10332/59.72254n   0.32724/59.97801n
R_load = 50.000000
[Rising Waveform]
R_fixture= 50.000000
V_fixture= 2.400000
V_fixture_min= 2.000000
V_fixture_max= 2.700000
|time   V(typ)   V(min)   V(max)
0s        2.046V     1.827V     2.154V
24.82us   2.046V     1.827V     2.154V
25.03us   2.046V     1.827V     2.7V
37.64us   2.046V     1.827V     2.7V
37.84us   2.4V       1.827V     2.7V
65.07us   2.401V     1.827V     2.7V
65.27us   2.401V     2.001V     2.7V
65.67us   2.401V     2.002V     2.7V
66.07us   2.401V     1.998V     2.7V
99.7us    2.4V       2V         2.7V
[Falling Waveform]
R_fixture= 50.000000
V_fixture= 2.400000
V_fixture_min= 2.000000
V_fixture_max= 2.700000
|time   V(typ)   V(min)   V(max)
0s        2.4V       2V         2.7V
20.02ns   2.047V     1.826V     2.154V
520.5ns   2.046V     1.827V     2.154V
9.97us    2.046V     1.827V     2.154V
